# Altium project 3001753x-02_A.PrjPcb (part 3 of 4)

## Sheet 12 - MIPI to HDMI bridge.SchDoc: MIPI to HDMI bridge
size A3; PageSetup: Record=PageOptions¦CenterHorizontal=True¦CenterVertical=True¦PrintScale=0.70¦XCorrection=1.00¦YCorrection=1.00¦PrintKind=0¦BorderSize=5000000¦LeftOffset=0¦BottomOffset=0¦Orientation=2¦PaperLength=4200¦PaperWidth=2970¦Scale=100¦PaperSource=7¦PrintQuality=600¦MediaType=1¦DitherType=10¦PaperKind=A4¦PrintScaleMode=1; Author: Juan Anzola; SheetNumber: 12; SheetTotal: 20

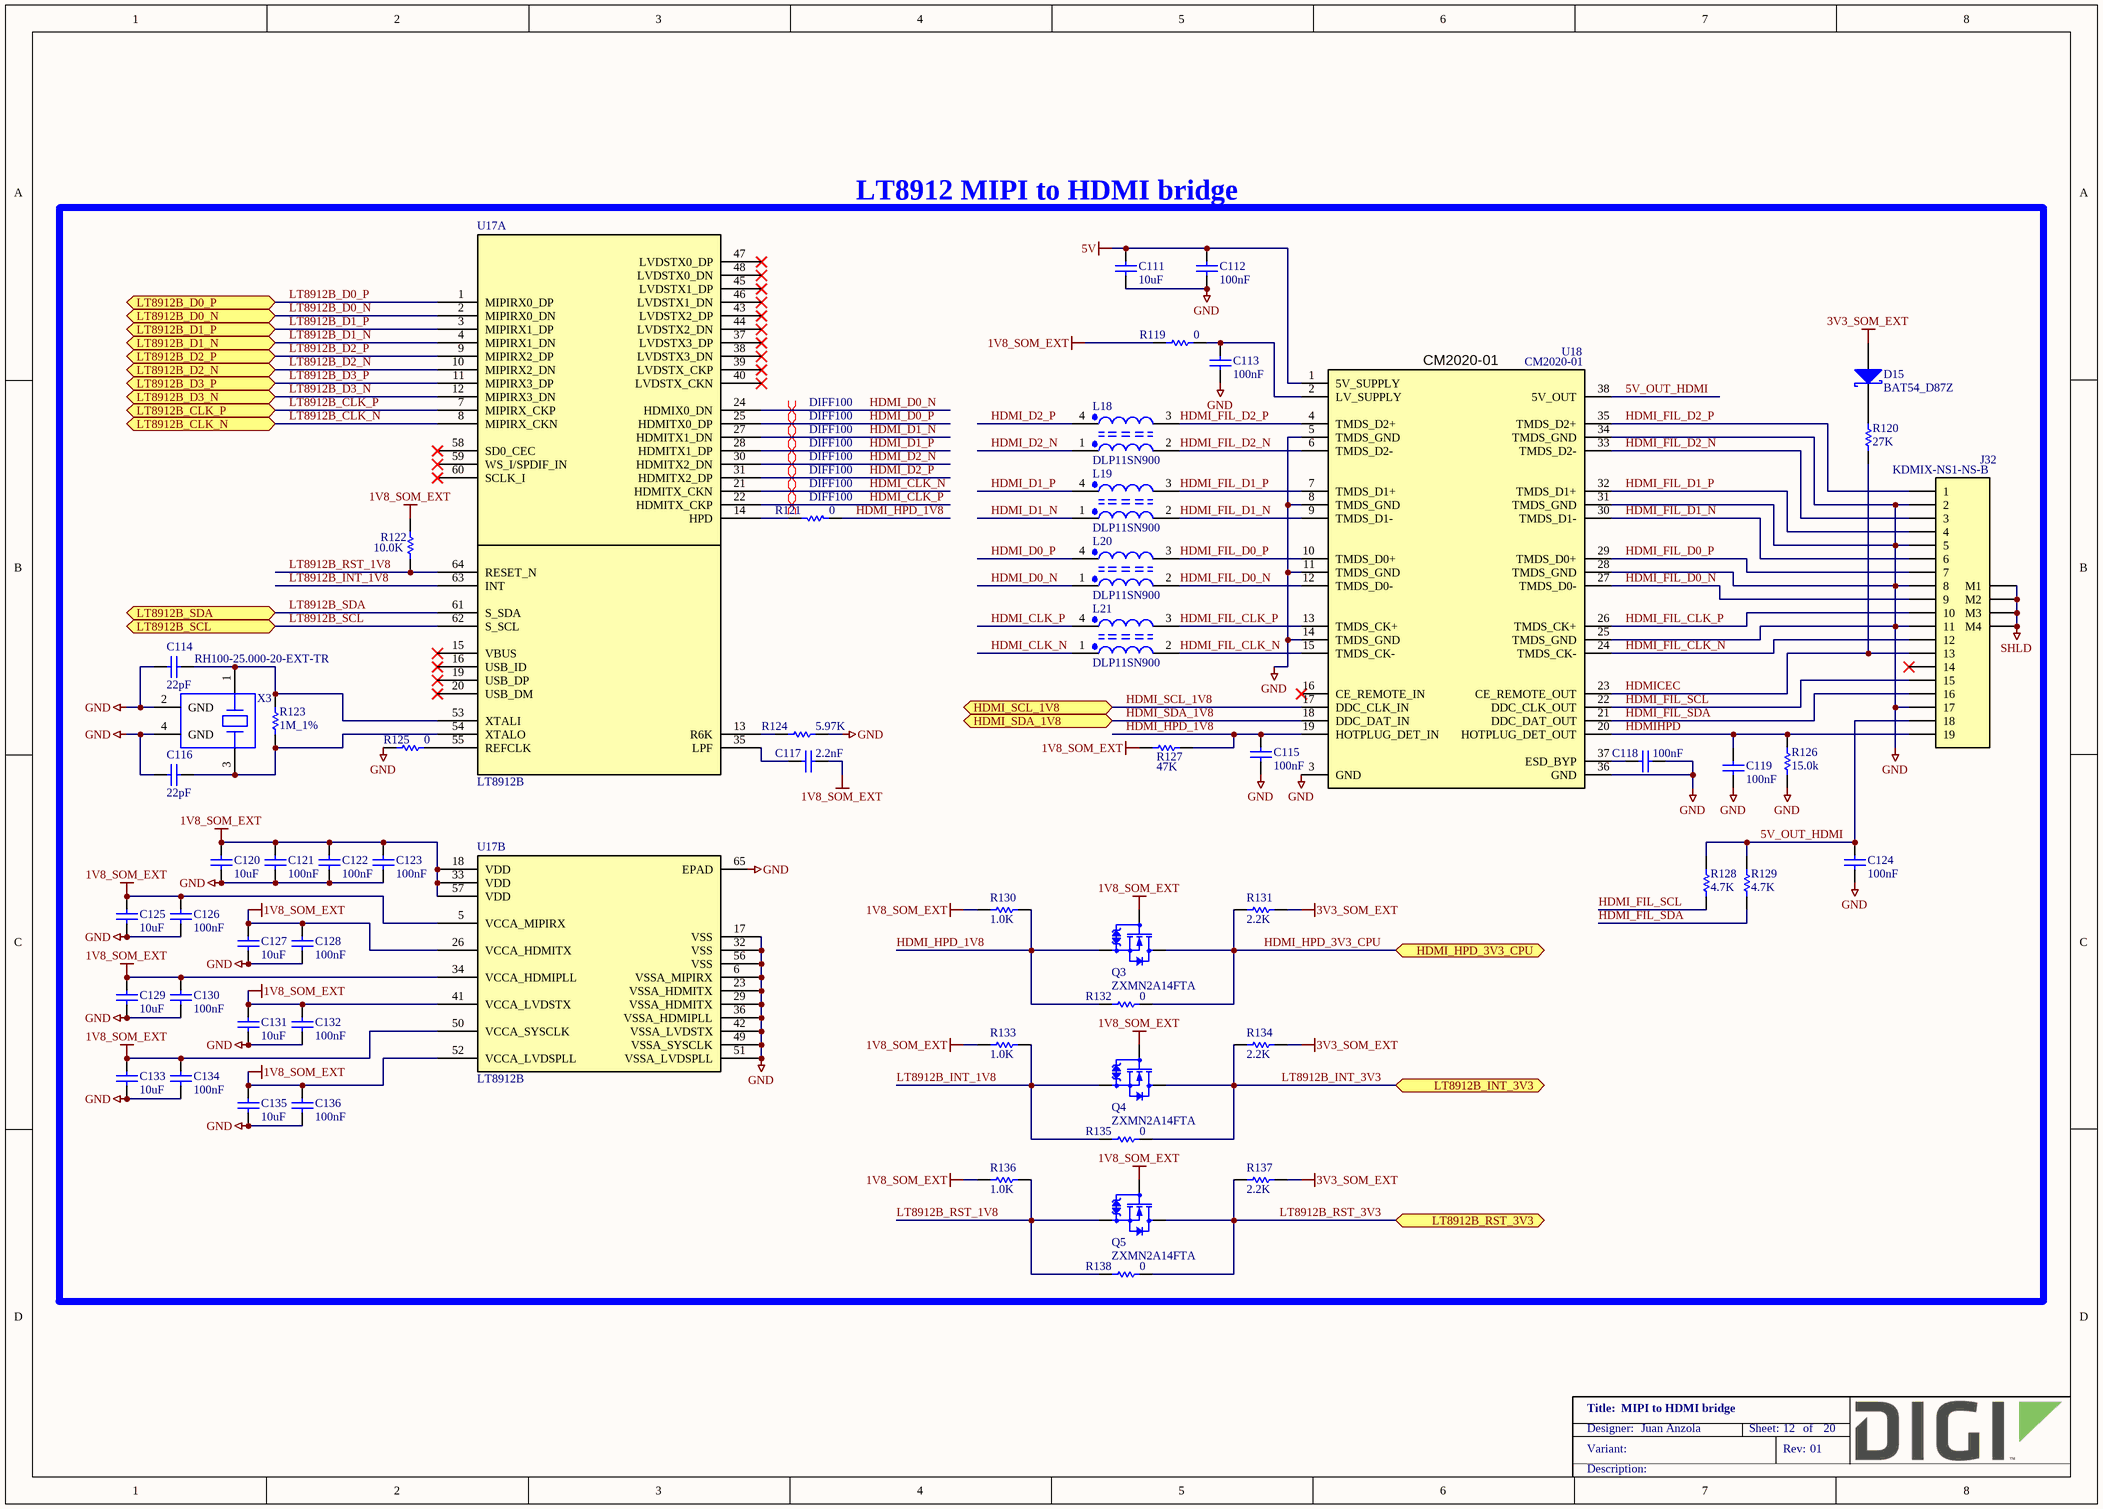
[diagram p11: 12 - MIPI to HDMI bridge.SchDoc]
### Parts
C111  10uF  [CAPC1005X55N]
C112  100nF  [CAPC1005X55N]
C113  100nF  [CAPC1005X55N]
C114  22pF  [CAPC1005X55N]
C115  100nF  [CAPC1005X55N]
C116  22pF  [CAPC1005X55N]
C117  2.2nF  [CAPC1608X90N]
C118  100nF  [CAPC1005X55N]
C119  100nF  [CAPC1005X55N]
C120  10uF  [CAPC1005X55N]
C121  100nF  [CAPC1005X55N]
C122  100nF  [CAPC1005X55N]
C123  100nF  [CAPC1005X55N]
C124  100nF  [CAPC1005X55N]
C125  10uF  [CAPC1005X55N]
C126  100nF  [CAPC1005X55N]
C127  10uF  [CAPC1005X55N]
C128  100nF  [CAPC1005X55N]
C129  10uF  [CAPC1005X55N]
C130  100nF  [CAPC1005X55N]
C131  10uF  [CAPC1005X55N]
C132  100nF  [CAPC1005X55N]
C133  10uF  [CAPC1005X55N]
C134  100nF  [CAPC1005X55N]
C135  10uF  [CAPC1005X55N]
C136  100nF  [CAPC1005X55N]
D15  BAT54_D87Z  [SOT95P240X110_AXK-3N]
J32  KDMIX-NS1-NS-B  [KYCON_KDMIX]
L18  DLP11SN900  [FIL_DLP11S]
L19  DLP11SN900  [FIL_DLP11S]
L20  DLP11SN900  [FIL_DLP11S]
L21  DLP11SN900  [FIL_DLP11S]
Q3  ZXMN2A14FTA  [SOT95P240X110_GSD-3N]
Q4  ZXMN2A14FTA  [SOT95P240X110_GSD-3N]
Q5  ZXMN2A14FTA  [SOT95P240X110_GSD-3N]
R119  0  [RESC1005X40N]
R120  27K  [RESC1005X40N]
R121  0  [RESC1005X40N]
R122  10.0K  [RESC1005X40N]
R123  1M_1%  [RESC1005X40N]
R124  5.97K  [RESC1005X40N]
R125  0  [RESC1005X40N]
R126  15.0k  [RESC1005X40N]
R127  47K  [RESC1005X40N]
R128  4.7K  [RESC1005X40N]
R129  4.7K  [RESC1005X40N]
R130  1.0K  [RESC1005X40N]
R131  2.2K  [RESC1005X40N]
R132  0  [RESC1005X40N]
R133  1.0K  [RESC1005X40N]
R134  2.2K  [RESC1005X40N]
R135  0  [RESC1005X40N]
R136  1.0K  [RESC1005X40N]
R137  2.2K  [RESC1005X40N]
R138  0  [RESC1005X40N]
U17  LT8912B  [QFN40P750X750X80-65T620N]  (parts A,B of 2)
U18  CM2020-01  [SOP50P640X120-38N]
X3  RH100-25.000-20-EXT-TR  [OSC210P320X250X90-4N]

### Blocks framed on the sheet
LT8912 MIPI to HDMI bridge: C111-C136 D15 J32 L18-L21 Q3-Q5 R119-R138 U17 U18 X3

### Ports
HDMI_HPD_3V3_CPU (bidir), HDMI_SCL_1V8 (bidir), HDMI_SDA_1V8 (bidir), LT8912B_CLK_N (bidir), LT8912B_CLK_P (bidir), LT8912B_D0_N (bidir), LT8912B_D0_P (bidir), LT8912B_D1_N (bidir), LT8912B_D1_P (bidir), LT8912B_D2_N (bidir), LT8912B_D2_P (bidir), LT8912B_D3_N (bidir), LT8912B_D3_P (bidir), LT8912B_INT_3V3 (bidir), LT8912B_RST_3V3 (bidir), LT8912B_SCL (bidir), LT8912B_SDA (bidir)

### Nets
1V8_SOM_EXT: C117.2 C120.2 C121.2 C122.2 C123.2 C125.2 C126.2 C127.2 C128.2 C129.2 C130.2 C131.2 C132.2 C133.2 C134.2 C135.2 C136.2 Q3.G Q4.G Q5.G R119.2 R122.1 R127.1 R130.2 R133.2 R136.2 U17.5(VCCA_MIPIRX) U17.18(VDD) U17.26(VCCA_HDMITX) U17.33(VDD) U17.34(VCCA_HDMIPLL) U17.41(VCCA_LVDSTX) U17.50(VCCA_SYSCLK) U17.52(VCCA_LVDSPLL) U17.57(VDD)
3V3_SOM_EXT: D15.A R131.2 R134.2 R137.2
5V: C111.2 C112.2 U18.1(5V_SUPPLY)
GND: C111.1 C112.1 C113.1 C114.1 C115.1 C116.1 C118.1 C119.1 C120.1 C121.1 C122.1 C123.1 C124.1 C125.1 C126.1 C127.1 C128.1 C129.1 C130.1 C131.1 C132.1 C133.1 C134.1 C135.1 C136.1 J32.2 J32.5 J32.8 J32.11 J32.17 R124.2 R125.1 R126.1 U17.6(VSSA_MIPIRX) U17.17(VSS) U17.23(VSSA_HDMITX) U17.29(VSSA_HDMITX) U17.32(VSS) U17.36(VSSA_HDMIPLL) U17.42(VSSA_LVDSTX) U17.49(VSSA_SYSCLK) U17.51(VSSA_LVDSPLL) U17.56(VSS) U17.65(EPAD) U18.3(GND) U18.5(TMDS_GND) U18.8(TMDS_GND) U18.11(TMDS_GND) U18.14(TMDS_GND) U18.25(TMDS_GND) U18.28(TMDS_GND) U18.31(TMDS_GND) U18.34(TMDS_GND) U18.36(GND) X3.2(GND) X3.4(GND)
SHLD: J32.M1 J32.M2 J32.M3 J32.M4
5V_OUT_HDMI: C124.2 J32.18 R128.1 R129.1 U18.38(5V_OUT)
HDMI_CLK_N: L21.1 U17.21(HDMITX_CKN)
HDMI_CLK_P: L21.4 U17.22(HDMITX_CKP)
HDMI_D0_N: L20.1 U17.24(HDMIX0_DN)
HDMI_D0_P: L20.4 U17.25(HDMITX0_DP)
HDMI_D1_N: L19.1 U17.27(HDMITX1_DN)
HDMI_D1_P: L19.4 U17.28(HDMITX1_DP)
HDMI_D2_N: L18.1 U17.30(HDMITX2_DN)
HDMI_D2_P: L18.4 U17.31(HDMITX2_DP)
HDMI_FIL_CLK_N: J32.12 L21.2 U18.15(TMDS_CK-) U18.24(TMDS_CK-)
HDMI_FIL_CLK_P: J32.10 L21.3 U18.13(TMDS_CK+) U18.26(TMDS_CK+)
HDMI_FIL_D0_N: J32.9 L20.2 U18.12(TMDS_D0-) U18.27(TMDS_D0-)
HDMI_FIL_D0_P: J32.7 L20.3 U18.10(TMDS_D0+) U18.29(TMDS_D0+)
HDMI_FIL_D1_N: J32.6 L19.2 U18.9(TMDS_D1-) U18.30(TMDS_D1-)
HDMI_FIL_D1_P: J32.4 L19.3 U18.7(TMDS_D1+) U18.32(TMDS_D1+)
HDMI_FIL_D2_N: J32.3 L18.2 U18.6(TMDS_D2-) U18.33(TMDS_D2-)
HDMI_FIL_D2_P: J32.1 L18.3 U18.4(TMDS_D2+) U18.35(TMDS_D2+)
HDMI_FIL_SCL: J32.15 R128.2 U18.22(DDC_CLK_OUT)
HDMI_FIL_SDA: J32.16 R129.2 U18.21(DDC_DAT_OUT)
HDMI_HPD_1V8: C115.2 Q3.S R121.1 R127.2 R130.1 R132.1 U18.19(HOTPLUG_DET_IN)
HDMI_HPD_3V3_CPU: Q3.D R131.1 R132.2 ; port HDMI_HPD_3V3_CPU
HDMI_SCL_1V8: U18.17(DDC_CLK_IN) ; port HDMI_SCL_1V8
HDMI_SDA_1V8: U18.18(DDC_DAT_IN) ; port HDMI_SDA_1V8
HDMICEC: J32.13 R120.2 U18.23(CE_REMOTE_OUT)
HDMIHPD: C119.2 J32.19 R126.2 U18.20(HOTPLUG_DET_OUT)
LT8912B_CLK_N: U17.8(MIPIRX_CKN) ; port LT8912B_CLK_N
LT8912B_CLK_P: U17.7(MIPIRX_CKP) ; port LT8912B_CLK_P
LT8912B_D0_N: U17.2(MIPIRX0_DN) ; port LT8912B_D0_N
LT8912B_D0_P: U17.1(MIPIRX0_DP) ; port LT8912B_D0_P
LT8912B_D1_N: U17.4(MIPIRX1_DN) ; port LT8912B_D1_N
LT8912B_D1_P: U17.3(MIPIRX1_DP) ; port LT8912B_D1_P
LT8912B_D2_N: U17.10(MIPIRX2_DN) ; port LT8912B_D2_N
LT8912B_D2_P: U17.9(MIPIRX2_DP) ; port LT8912B_D2_P
LT8912B_D3_N: U17.12(MIPIRX3_DN) ; port LT8912B_D3_N
LT8912B_D3_P: U17.11(MIPIRX3_DP) ; port LT8912B_D3_P
LT8912B_INT_1V8: Q4.S R133.1 R135.1 U17.63(INT)
LT8912B_INT_3V3: Q4.D R134.1 R135.2 ; port LT8912B_INT_3V3
LT8912B_RST_1V8: Q5.S R122.2 R136.1 R138.1 U17.64(RESET_N)
LT8912B_RST_3V3: Q5.D R137.1 R138.2 ; port LT8912B_RST_3V3
LT8912B_SCL: U17.62(S_SCL) ; port LT8912B_SCL
LT8912B_SDA: U17.61(S_SDA) ; port LT8912B_SDA
NetC113_2: C113.2 R119.1 U18.2(LV_SUPPLY)
NetC114_2: C114.2 R123.2 U17.53(XTALI) X3.1
NetC116_2: C116.2 R123.1 U17.54(XTALO) X3.3
NetC117_1: C117.1 U17.35(LPF)
NetC118_2: C118.2 U18.37(ESD_BYP)
NetD15_K: D15.K R120.1
NetR121_2: R121.2 U17.14(HPD)
NetR124_1: R124.1 U17.13(R6K)
NetR125_2: R125.2 U17.55(REFCLK)

Not connected (* = marked no-connect by the designer): J32 14*; U17 15(VBUS)* 16(USB_ID)* 19(USB_DP)* 20(USB_DM)* 37(LVDSTX3_DP)* 38(LVDSTX3_DN)* 39(LVDSTX_CKP)* 40(LVDSTX_CKN)* 43(LVDSTX2_DP)* 44(LVDSTX2_DN)* 45(LVDSTX1_DP)* 46(LVDSTX1_DN)* 47(LVDSTX0_DP)* 48(LVDSTX0_DN)* 58(SD0_CEC)* 59(WS_I/SPDIF_IN)* 60(SCLK_I)*; U18 16(CE_REMOTE_IN)*

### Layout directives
differential pair; net class DIFF100; differential pair class DIFF100: HDMI_CLK_N, HDMI_CLK_P, HDMI_D0_N, HDMI_D0_P, HDMI_D1_N, HDMI_D1_P, HDMI_D2_N, HDMI_D2_P

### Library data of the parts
C111 C120 C125 C127 C129 C131 C133 C135 = 1001168: CAP CER 10UF 10V 20% X5R 0402; Part_Type: Capacitor; Manufacturer: Samsung; Manufacturer_Part_Number: CL05A106MP5NUNC; Digi_PN: 14050689; Component_Life_Cycle_State: Reviewed; Area: 0.95; Project: CCWMX6_SBC board
C112 C113 C115 C118 C119 C121-C124 C126 C128 C130 C132 C134 C136 = 1000006: CAP 100nF 16V 10% X7R 0402; Part_Type: Capacitor; Manufacturer: Murata; Manufacturer_Part_Number: GRM155R71C104KA88D; Component_Life_Cycle_State: CAD Reviewed; Area: 0.95; Project: KITT; Tolerance: 10; Digi_PN: 14050552
C114 C116 = 1001166: CAP CER 22PF 50V 5% NP0 0402; Part_Type: Capacitor; Manufacturer: Murata; Manufacturer_Part_Number: GRM1555C1H220JA01D; Note: 14050749 = Digi No. for GE WDNU; Digi_PN: 14050367; Component_Life_Cycle_State: Reviewed; Area: 0,95; Project: CCWMX6_SBC board; Temp_Coef: C0G, NP0
C117 = 1002727: CAP CER 2200PF 50V X7R 5% 0603; Part_Type: Capacitor; Manufacturer: Kemet; Manufacturer_Part_Number: C0603C222J5RACTU; Digi_PN: 14050443; Component_Life_Cycle_State: Pending; Area: 2,27
D15 = 1001169: DIODE SCHOTTKY 30V 0.2A SOT23-3; Part_Type: IC; Manufacturer: Fairchild Semiconductor; Digi_PN: 17050507; Component_Life_Cycle_State: Reviewed; Area: 8; Project: CCWMX6_SBC board
J32 = 1001123: HDMI RECEPTACLE, SMT; Part_Type: Connector; Manufacturer: KYCON; Digi_PN: 18000451; Component_Life_Cycle_State: Reviewed; Area: 174; Project: CCWMX6_SBC board
L18-L21 = 1001014: CHOKE COIL COMMON MODE 150MA SMD; Part_Type: Inductor; Manufacturer: Murata; Manufacturer_Part_Number: DLP11SN900HL2L; Component_Life_Cycle_State: Reviewed; Area: 3.94; Project: ResMed RF Test Interface Board; Digi_PN: 21000531
Q3-Q5 = 1002855: MOSFET N-CH 20V 3.4A SOT23-3; Part_Type: Transistor; Manufacturer: Diodes, Inc.; Digi_PN: 17000304; Component_Life_Cycle_State: Pending
R119 R121 R125 = 1000076: RES 0.0 OHM 1/10W 0402 SMD; Part_Type: Resistor; Manufacturer: Panasonic - ECG; Manufacturer_Part_Number: ERJ-2GE0R00X; Digi_PN: 13050387; Component_Life_Cycle_State: Proven; Area: 0,95; Project: Adjustable Foundation; Power_WV_SRF: 10
R120 = 1001153: RES 27.0K OHM 1/16W 1% 0402 SMD; Part_Type: Resistor; Manufacturer: Yageo; Manufacturer_Part_Number: RC0402FR-0727KL; Digi_PN: 13050609; Component_Life_Cycle_State: Reviewed; Area: 0.95; Project: CCWMX6_SBC board
R122 = 1000537: RES 10.0K OHM 1/10W 1% 0402 SMD; Part_Type: Resistor; Manufacturer: Panasonic - ECG; Manufacturer_Part_Number: ERJ-2RKF1002X; Component_Life_Cycle_State: CAD Reviewed; Area: 0.95; Project: KITT; Power_WV_SRF: 100; Digi_PN: 13051084
R123 = 1000971: RES 1.00M OHM 1/16W 1% 0402 SMD; Part_Type: Resistor; Manufacturer: Yageo; Manufacturer_Part_Number: RC0402FR-071ML; Note: 13051098 = Digi No. for GE WDNU; Digi_PN: 13050561; Component_Life_Cycle_State: Reviewed; Area: 0,95; Power_WV_SRF: 63; Tolerance: 1
R124 = 1002748: RES 5.97K OHM 0.1% 1/10W 0402; Part_Type: Resistor; Manufacturer: Vishay Dale; Manufacturer_Part_Number: TNPW04025K97BEED; Digi_PN: 13000099; Component_Life_Cycle_State: Created; Area: 0,95
R126 = 1000174: RES 15.0K OHM 1/10W 1% 0402 SMD; Part_Type: Resistor; Manufacturer: Panasonic - ECG; Manufacturer_Part_Number: ERJ-2RKF1502X; Component_Life_Cycle_State: CAD Reviewed; Area: 0.95; Project: KITT; Power_WV_SRF: 10; Digi_PN: 13050446
R127 = 1001155: RES 47.0K OHM 1/16W 1% 0402 SMD; Part_Type: Resistor; Manufacturer: Vishay Dale; Manufacturer_Part_Number: CRCW040247K0FKED; Digi_PN: 13050646; Component_Life_Cycle_State: Reviewed; Area: 0.95; Project: CCWMX6_SBC board
R128 R129 = 1000038: RES 4.7K OHM 1/10W 5% 0402 SMD; Part_Type: Resistor; Manufacturer: Panasonic - ECG; Manufacturer_Part_Number: ERJ-2GEJ472X; Component_Life_Cycle_State: Proven; Area: 0.95; Project: Adjustable Foundation; Power_WV_SRF: 100; Tolerance: 5; Digi_PN: 13050549
R130 R133 R136 = 1000079: RES 1.00K OHM 1/10W 1% 0402 SMD; Part_Type: Resistor; Manufacturer: Panasonic - ECG; Manufacturer_Part_Number: ERJ-2RKF1001X; Digi_PN: 13051085; Component_Life_Cycle_State: Proven; Area: 0,95; Project: Adjustable Foundation; Power_WV_SRF: 10
R131 R134 R137 = 1001156: RES 2.20K OHM 1/16W 1% 0402 SMD; Part_Type: Resistor; Manufacturer: Yageo; Manufacturer_Part_Number: RC0402FR-072K2L; Note: 13051099 = Digi No. for GE WDNU; Digi_PN: 13050699; Component_Life_Cycle_State: Reviewed; Area: 0,95
R132 R135 R138 = 1000076: RES 0.0 OHM 1/10W 0402 SMD; Part_Type: Resistor; Manufacturer: Panasonic - ECG; Manufacturer_Part_Number: ERJ-2GE0R00X; Digi_PN: 13050387; Component_Life_Cycle_State: Proven; Area: 0,95; Power_WV_SRF: 10
U17 = 1002722: MIPI DSI BRIDGE TO LVDS/HDMI SINGLE CHANNEL; Part_Type: IC; Manufacturer: Lontium Semiconductor; Digi_PN: 16000199; Component_Life_Cycle_State: Reviewed; Area: 76,04
U18 = 1001125: IC HDMI XMITTER PORT P/I 38TSSOP; Manufacturer: On Semiconductor; Digi_PN: 16051861; Component_Life_Cycle_State: Reviewed; Area: 43; Project: CCWMX6_SBC board
X3 = 1001497: SMCRY,25MHZ 50PPM 20PF RH100 EXT; Part_Type: Crystals-Oscillators; Manufacturer: Raltron; Digi_PN: 20000285; Component_Life_Cycle_State: Reviewed; Area: 3,2; Project: CCWMX6_SBC board

## Sheet 13 - USB HUB.SchDoc: USB HUB
size A3; PageSetup: Record=PageOptions¦CenterHorizontal=True¦CenterVertical=True¦PrintScale=0.70¦XCorrection=1.00¦YCorrection=1.00¦PrintKind=0¦BorderSize=5000000¦LeftOffset=0¦BottomOffset=0¦Orientation=2¦PaperLength=4200¦PaperWidth=2970¦Scale=100¦PaperSource=7¦PrintQuality=600¦MediaType=1¦DitherType=10¦PaperKind=A4¦PrintScaleMode=1; Author: Juan Anzola; SheetNumber: 13; SheetTotal: 20

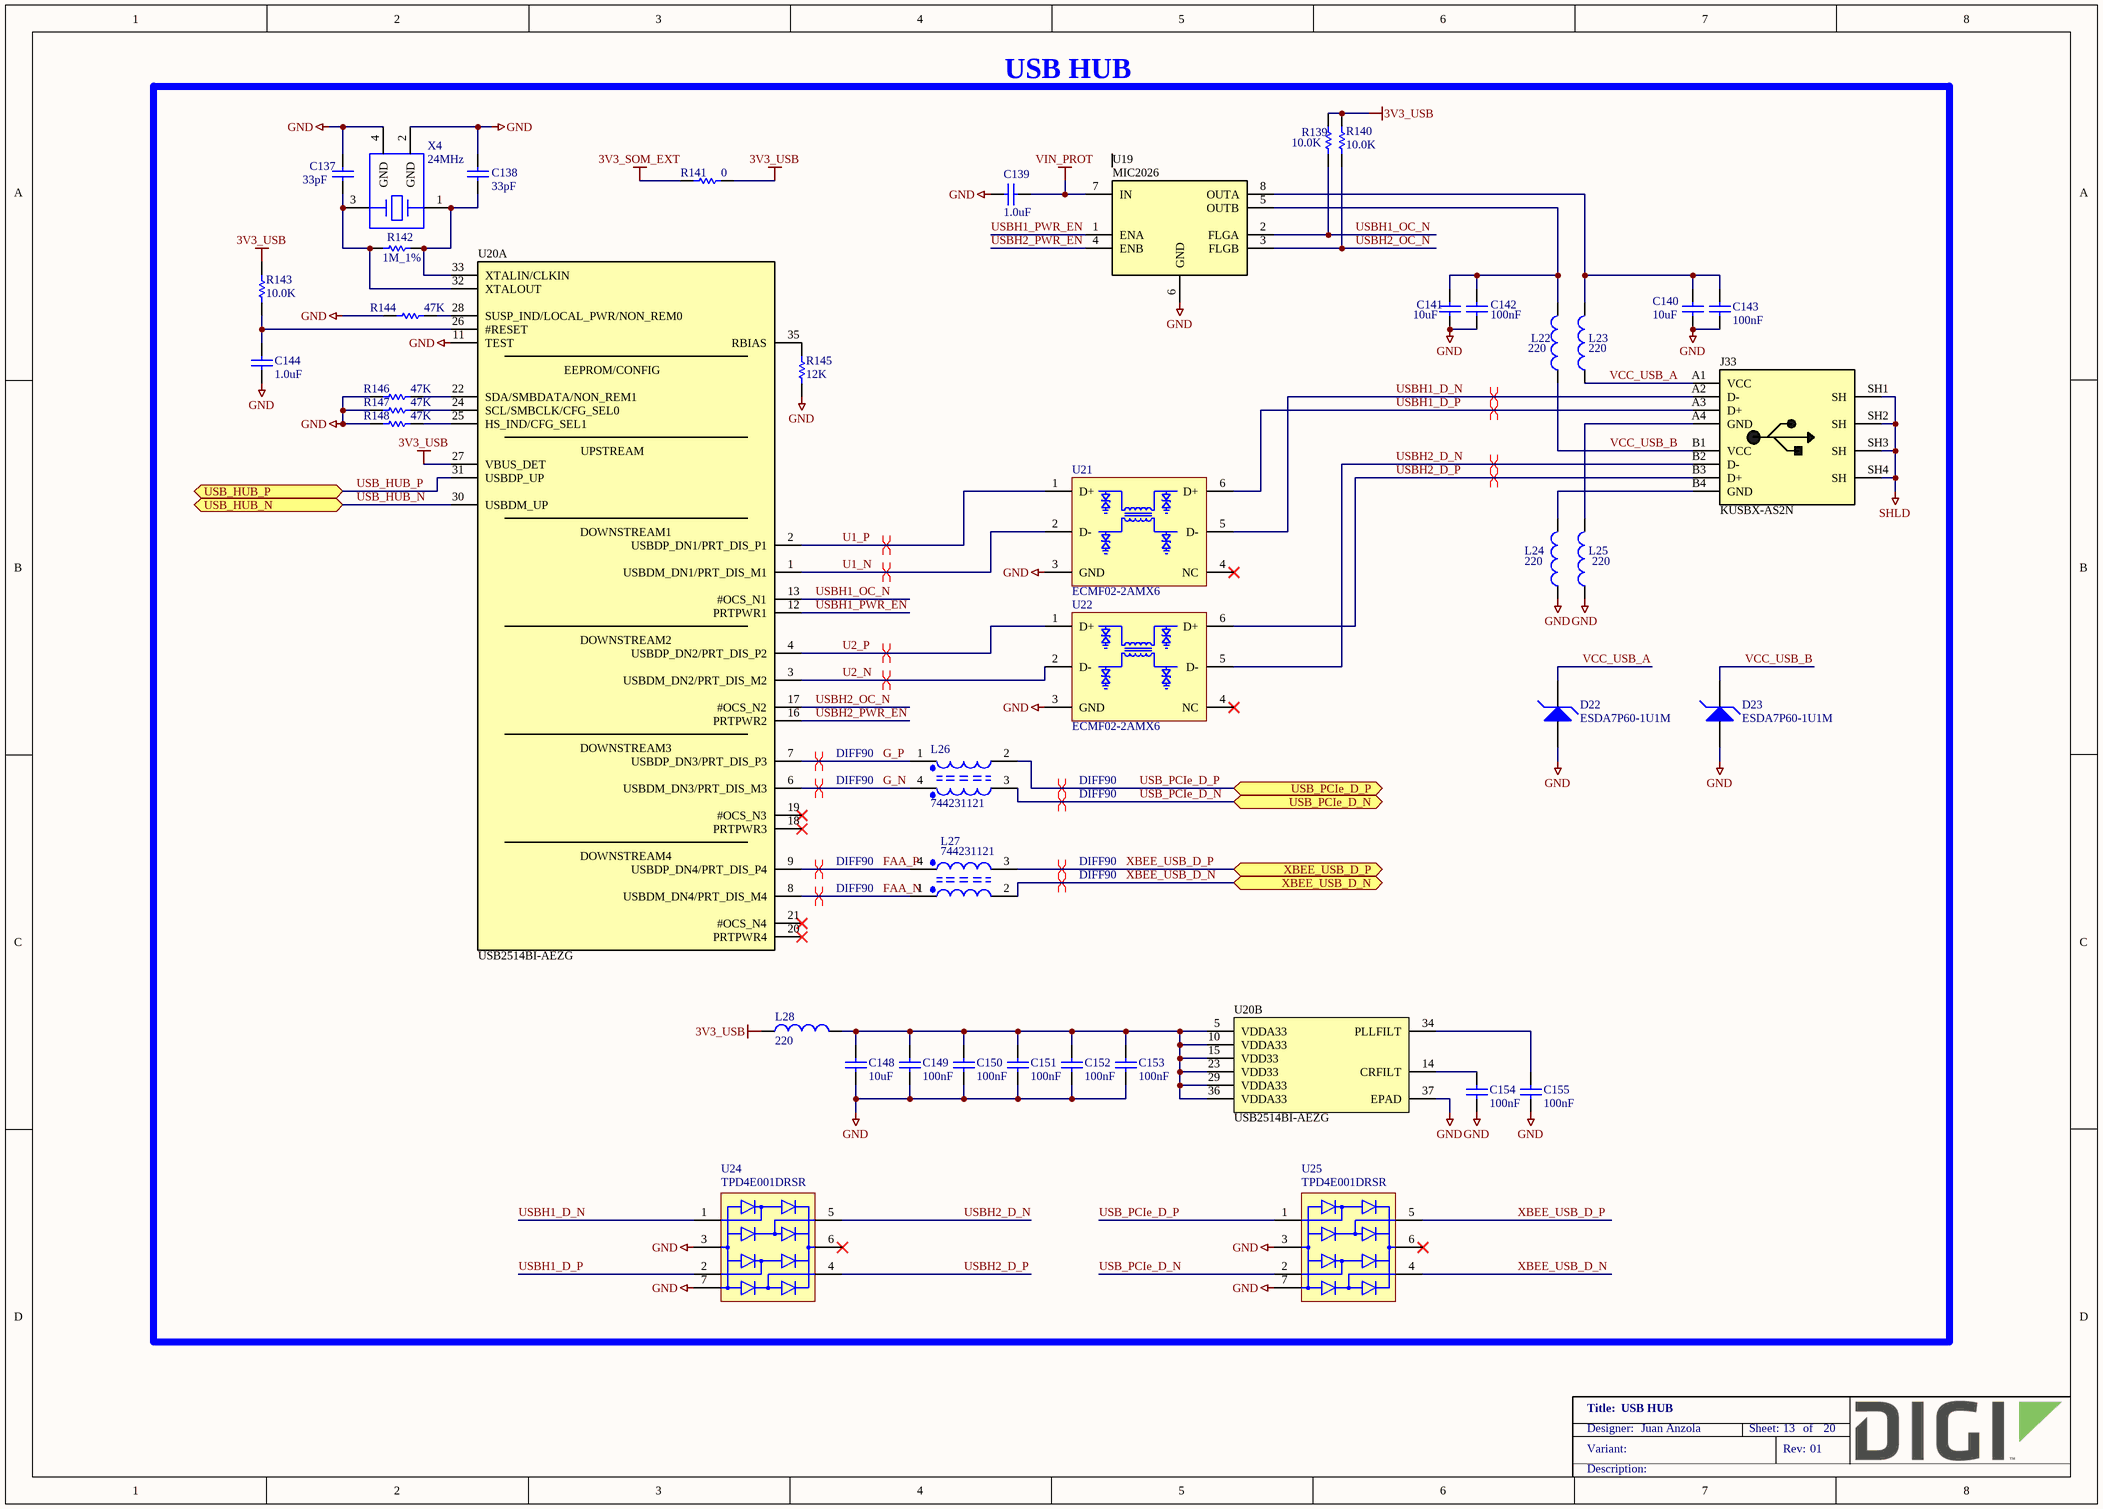
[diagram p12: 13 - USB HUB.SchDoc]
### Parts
C137  33pF  [CAPC1005X55N]
C138  33pF  [CAPC1005X55N]
C139  1.0uF  [CAPC1005X55N]
C140  10uF  [CAPC1005X55N]
C141  10uF  [CAPC1005X55N]
C142  100nF  [CAPC1005X55N]
C143  100nF  [CAPC1005X55N]
C144  1.0uF  [CAPC1005X55N]
C148  10uF  [CAPC1005X55N]
C149  100nF  [CAPC1005X55N]
C150  100nF  [CAPC1005X55N]
C151  100nF  [CAPC1005X55N]
C152  100nF  [CAPC1005X55N]
C153  100nF  [CAPC1005X55N]
C154  100nF  [CAPC1005X55N]
C155  100nF  [CAPC1005X55N]
D22  ESDA7P60-1U1M  [IND_1610]
D23  ESDA7P60-1U1M  [IND_1610]
J33  KUSBX-AS2N  [KYCON_KUSBX-AS2N_Flex]
L22  220  [INDC2013X110N]
L23  220  [INDC2013X110N]
L24  220  [INDC2013X110N]
L25  220  [INDC2013X110N]
L26  744231121  [FIL_DLW21H]
L27  744231121  [FIL_DLW21H]
L28  220  [INDC2013X110N]
R139  10.0K  [RESC1005X40N]
R140  10.0K  [RESC1005X40N]
R141  0  [RESC1609X55N]
R142  1M_1%  [RESC1005X40N]
R143  10.0K  [RESC1005X40N]
R144  47K  [RESC1005X40N]
R145  12K  [RESC1609X55N]
R146  47K  [RESC1005X40N]
R147  47K  [RESC1005X40N]
R148  47K  [RESC1005X40N]
U19  MIC2026  [SOIC127P600X175-8N]
U20  USB2514BI-AEZG  [QFN50P600X600X100-37AN]  (parts A,B of 2)
U21  ECMF02-2AMX6  [QFN_6L_1.7mmX1.5mm_STM]
U22  ECMF02-2AMX6  [QFN_6L_1.7mmX1.5mm_STM]
U24  TPD4E001DRSR  [SON95P300X300X80-7N]
U25  TPD4E001DRSR  [SON95P300X300X80-7N]
X4  24MHz  [XTAL_C3E-3427]

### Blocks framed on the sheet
USB HUB: C137-C144 C148-C155 D22 D23 J33 L22-L28 R139-R148 U19-U22 U24 U25 X4

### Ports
USB_HUB_N (bidir), USB_HUB_P (bidir), USB_PCIe_D_N (bidir), USB_PCIe_D_P (bidir), XBEE_USB_D_N (bidir), XBEE_USB_D_P (bidir)

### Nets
3V3_SOM_EXT: R141.1
3V3_USB: L28.2 R139.2 R140.2 R141.2 R143.2 U20.27(VBUS_DET)
GND: C137.2 C138.2 C139.2 C140.1 C141.1 C142.1 C143.1 C144.1 C148.1 C149.1 C150.1 C151.1 C152.1 C153.1 C154.1 C155.1 D22.A D23.A L24.1 L25.1 R144.2 R145.1 R146.1 R147.1 R148.1 U19.6(GND) U20.11(TEST) U20.37(EPAD) U21.3(GND) U22.3(GND) U24.3(GND) U24.7(GND) U25.3(GND) U25.7(GND) X4.2(GND) X4.4(GND)
SHLD: J33.SH1(SH) J33.SH2(SH) J33.SH3(SH) J33.SH4(SH)
VIN_PROT: C139.1 U19.7(IN)
FAA_N: L27.1 U20.8(USBDM_DN4/PRT_DIS_M4)
FAA_P: L27.4 U20.9(USBDP_DN4/PRT_DIS_P4)
G_N: L26.4 U20.6(USBDM_DN3/PRT_DIS_M3)
G_P: L26.1 U20.7(USBDP_DN3/PRT_DIS_P3)
U1_N: U20.1(USBDM_DN1/PRT_DIS_M1) U21.2(D-)
U1_P: U20.2(USBDP_DN1/PRT_DIS_P1) U21.1(D+)
U2_N: U20.3(USBDM_DN2/PRT_DIS_M2) U22.2(D-)
U2_P: U20.4(USBDP_DN2/PRT_DIS_P2) U22.1(D+)
USB_HUB_N: U20.30(USBDM_UP) ; port USB_HUB_N
USB_HUB_P: U20.31(USBDP_UP) ; port USB_HUB_P
USB_PCIe_D_N: L26.3 U25.2(I/O) ; port USB_PCIe_D_N
USB_PCIe_D_P: L26.2 U25.1(I/O) ; port USB_PCIe_D_P
USBH1_D_N: J33.A2(D-) U21.5(D-) U24.1(I/O)
USBH1_D_P: J33.A3(D+) U21.6(D+) U24.2(I/O)
USBH1_OC_N: R139.1 U19.2(FLGA) U20.13(#OCS_N1)
USBH1_PWR_EN: U19.1(ENA) U20.12(PRTPWR1)
USBH2_D_N: J33.B2(D-) U22.5(D-) U24.5(I/O)
USBH2_D_P: J33.B3(D+) U22.6(D+) U24.4(I/O)
USBH2_OC_N: R140.1 U19.3(FLGB) U20.17(#OCS_N2)
USBH2_PWR_EN: U19.4(ENB) U20.16(PRTPWR2)
VCC_USB_A: D22.K J33.A1(VCC) L23.1
VCC_USB_B: D23.K J33.B1(VCC) L22.1
XBEE_USB_D_N: L27.2 U25.4(I/O) ; port XBEE_USB_D_N
XBEE_USB_D_P: L27.3 U25.5(I/O) ; port XBEE_USB_D_P
NetC137_1: C137.1 R142.1 U20.32(XTALOUT) X4.3
NetC138_1: C138.1 R142.2 U20.33(XTALIN/CLKIN) X4.1
NetC140_2: C140.2 C143.2 L23.2 U19.8(OUTA)
NetC141_2: C141.2 C142.2 L22.2 U19.5(OUTB)
NetC144_2: C144.2 R143.1 U20.26(#RESET)
NetC148_2: C148.2 C149.2 C150.2 C151.2 C152.2 C153.2 L28.1 U20.5(VDDA33) U20.10(VDDA33) U20.15(VDD33) U20.23(VDD33) U20.29(VDDA33) U20.36(VDDA33)
NetC154_2: C154.2 U20.14(CRFILT)
NetC155_2: C155.2 U20.34(PLLFILT)
NetJ33_A4: J33.A4(GND) L25.2
NetJ33_B4: J33.B4(GND) L24.2
NetR144_1: R144.1 U20.28(SUSP_IND/LOCAL_PWR/NON_REM0)
NetR145_2: R145.2 U20.35(RBIAS)
NetR146_2: R146.2 U20.22(SDA/SMBDATA/NON_REM1)
NetR147_2: R147.2 U20.24(SCL/SMBCLK/CFG_SEL0)
NetR148_2: R148.2 U20.25(HS_IND/CFG_SEL1)

Not connected (* = marked no-connect by the designer): U20 18(PRTPWR3)* 19(#OCS_N3)* 20(PRTPWR4)* 21(#OCS_N4)*; U21 4(NC)*; U22 4(NC)*; U24 6(VCC)*; U25 6(VCC)*

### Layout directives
differential pair; differential pair class DIFF90: U1_N, U1_P, U2_N, U2_P, USBH1_D_N, USBH1_D_P, USBH2_D_N, USBH2_D_P
differential pair; net class DIFF90; differential pair class DIFF90: FAA_N, FAA_P, G_N, G_P, USB_PCIe_D_N, USB_PCIe_D_P, XBEE_USB_D_N, XBEE_USB_D_P

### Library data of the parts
C137 C138 = 1002646: CAP CER 33PF 50V C0G/NP0 0402; Part_Type: Capacitor; Manufacturer: Murata; Manufacturer_Part_Number: GCM1555C1H330JA16D; Digi_PN: 14050400; Component_Life_Cycle_State: Reviewed; Area: 2,12; Voltage: 50; Tolerance: 5%
C139 C144 = 1001167: CAP CER 1UF 10V 10% X5R 0402; Part_Type: Capacitor; Manufacturer: Murata; Manufacturer_Part_Number: GRM155R61A105KE15D; Digi_PN: 14050399; Component_Life_Cycle_State: Reviewed; Area: 0.95; Project: CCWMX6_SBC board
C140 C141 C148 = 1001168: as C111 on sheet 12 - MIPI to HDMI bridge
C142 C143 C149-C155 = 1000006: as C112 on sheet 12 - MIPI to HDMI bridge
D22 D23 = 1002861: TVS DIODE 5VWM 11.6VC 1610; Part_Type: Diodes; Manufacturer: STMicroelectronics; Digi_PN: 17000341; Component_Life_Cycle_State: Pending
J33 = 1001121: USB Stacked Dual A type; Part_Type: Connector; Manufacturer: KYCON; Digi_PN: 18000276; Component_Life_Cycle_State: Reviewed; Area: 164; Project: CCWMX6_SBC board
L22-L25 L28 = 1001174: FERRITE BEAD 220 OHM 2.0A 0805; Manufacturer: Wurth Electronics Inc; Manufacturer_Part_Number: 742792022; Digi_PN: 21000146; Component_Life_Cycle_State: Reviewed; Area: 4.24; Project: CCWMX6_SBC board
L26 L27 = 1001173: CHOKE COM MODE 120 OHM .37A; Part_Type: Inductor; Manufacturer: Wurth Electronics Inc; Digi_PN: 21000143; Component_Life_Cycle_State: Reviewed; Area: 2.4; Project: CCWMX6_SBC board
R139 R140 R143 = 1000537: as R122 on sheet 12 - MIPI to HDMI bridge
R141 = 1000208: RES 0.0 OHM 1/10W 0603; Part_Type: Resistor; Manufacturer: Panasonic - ECG; Manufacturer_Part_Number: ERJ-3GEY0R00V; Note: 13051103 = Digi No. for GE WDNU; Digi_PN: 13050568; Component_Life_Cycle_State: Reviewed; Area: 2.5; Project: Adjustable Foundation; Voltage: 75V
R142 = 1000971: RES 1.00M OHM 1/16W 1% 0402 SMD; Part_Type: Resistor; Manufacturer: Yageo; Manufacturer_Part_Number: RC0402FR-071ML; Digi_PN: 13050561; Component_Life_Cycle_State: Reviewed; Area: 0.95; Project: ConnectCore i.MX6 module; Power_WV_SRF: 63; Tolerance: 1; Note: 13051098 = Digi No. for GE WDNU
R144 R146-R148 = 1001155: as R127 on sheet 12 - MIPI to HDMI bridge
R145 = 1001200: RES 12.0K OHM 1/10W 1% 0603 SMD; Part_Type: Resistor; Manufacturer: Yageo; Manufacturer_Part_Number: RC0603FR-0712KL; Digi_PN: 13050531; Component_Life_Cycle_State: Reviewed; Area: 2.5; Project: LuCoV2; Power_WV_SRF: 100; Tolerance: 1
U19 = 1001143: IC SW DISTRIBUTION 2CHAN 8SOIC; Manufacturer: Micrel; Manufacturer_Part_Number: MIC2026-1YM; Digi_PN: 16051879; Component_Life_Cycle_State: Reviewed; Area: 29.58; Project: CCWMX6_SBC board
U20 = 1001114: 4-PORT USB 2.0 HUB CTRLR 36VQFN; Part_Type: IC; Manufacturer: SMSC; Digi_PN: 16051280; Component_Life_Cycle_State: Reviewed; Area: 36; Project: CCWMX6_SBC board
U21 U22 = 1002838: SMIC, COMMON MODE USB2.0/MIPI + ESD, QFN6, -40/+125°C
U24 U25 = 1001265: TVS DIODE 5.5VWM 6SON; Part_Type: IC; Manufacturer: Texas Instruments; Digi_PN: 17050690; Component_Life_Cycle_State: Reviewed; Area: 10; Project: CCWMX6_SBC board; Note: 17050839 = Digi No. for GE WDNU
X4 = 1001134: CRYSTAL 24MHZ 18PF SMD; Part_Type: Crystals-Oscillators; Manufacturer: Aker; Manufacturer_Part_Number: C3E-24.000-18-3030-X-R; Digi_PN: 20000223; Component_Life_Cycle_State: Reviewed; Area: 9.18; Project: CCWMX6_SBC board

## Sheet 14 - USB Type C.SchDoc: USB Type C, USB mciroAB
size A3; PageSetup: Record=PageOptions¦CenterHorizontal=True¦CenterVertical=True¦PrintScale=0.70¦XCorrection=1.00¦YCorrection=1.00¦PrintKind=0¦BorderSize=5000000¦LeftOffset=0¦BottomOffset=0¦Orientation=2¦PaperLength=4200¦PaperWidth=2970¦Scale=100¦PaperSource=7¦PrintQuality=600¦MediaType=1¦DitherType=10¦PaperKind=A4¦PrintScaleMode=1; Author: Juan Anzola; SheetNumber: 14; SheetTotal: 20

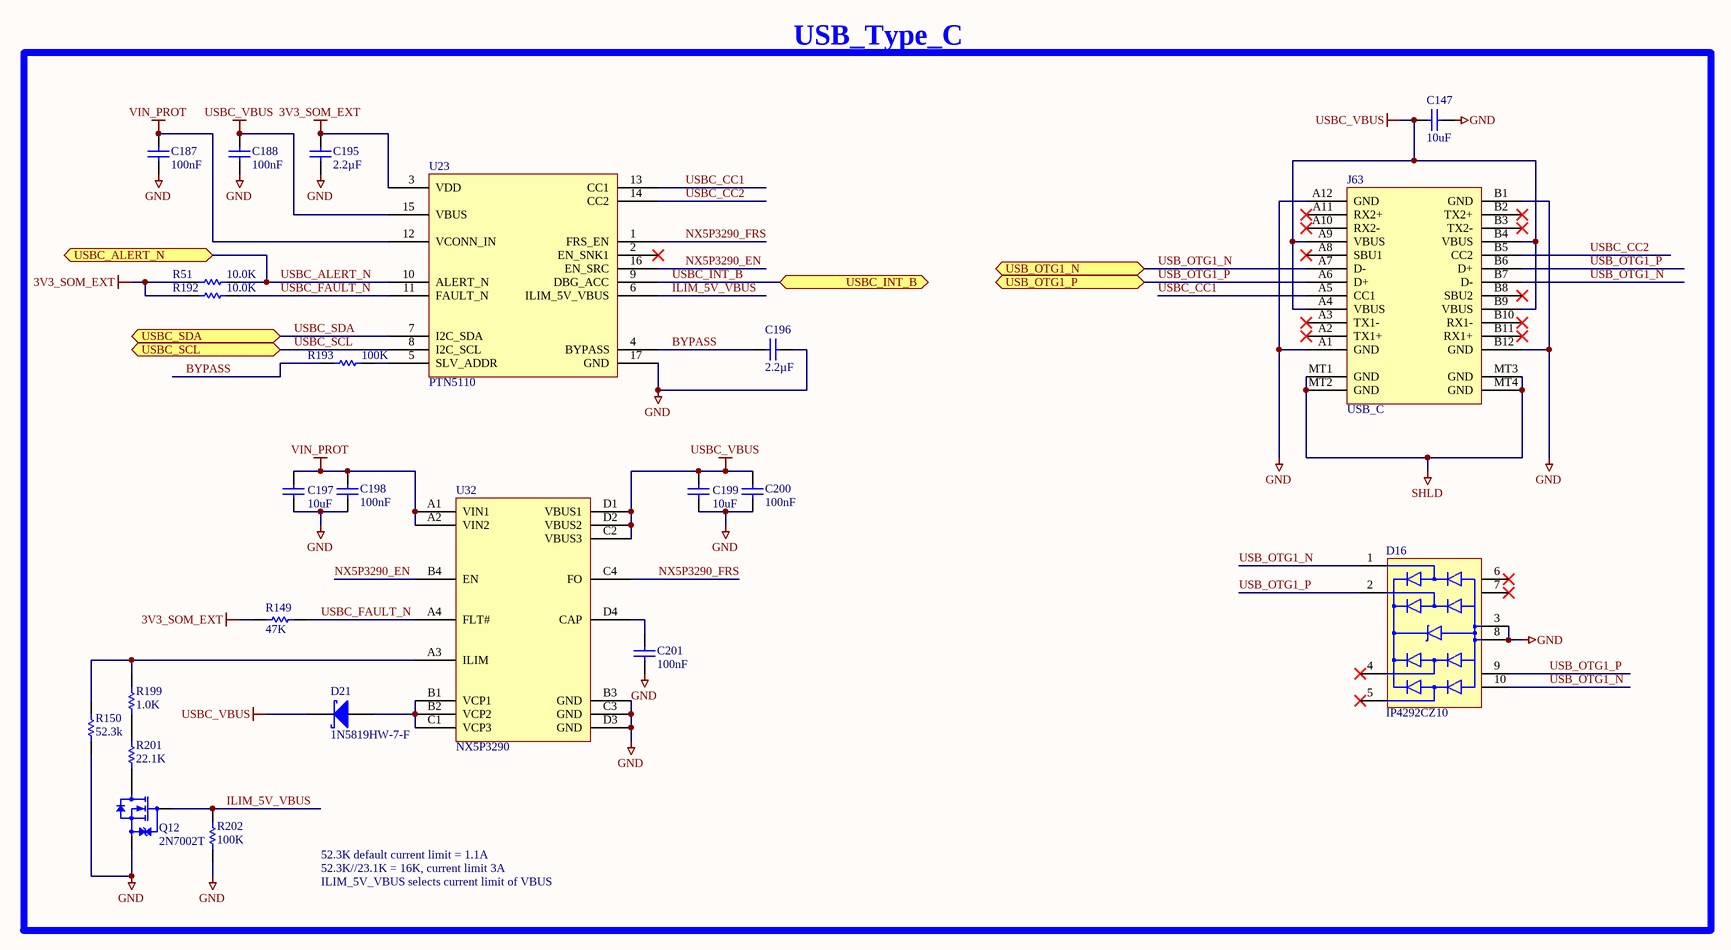
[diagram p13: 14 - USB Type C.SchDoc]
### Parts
C147  10uF  [CAPC1005X55N]
C187  100nF  [CAPC1005X55N]
C188  100nF  [CAPC1005X55N]
C195  2.2µF  [CAPC1005X55L]
C196  2.2µF  [CAPC1005X55L]
C197  10uF  [CAPC1005X55N]
C198  100nF  [CAPC1005X55N]
C199  10uF  [CAPC1005X55N]
C200  100nF  [CAPC1005X55N]
C201  100nF  [CAPC1005X55N]
D16  IP4292CZ10  [SON50P250X100X50-10N]
D21  1N5819HW-7-F  [SOD3716X135N]
J63  USB_C  [MOLEX_201267-0005]
Q12  2N7002T  [SOTFL50P160X80_GSD-3N]
R51  10.0K  [RESC1005X40N]
R149  47K  [RESC1005X40N]
R150  52.3k  [RESC1005X40N]
R192  10.0K  [RESC1005X40N]
R193  100K  [RESC1005X40N]
R199  1.0K  [RESC1005X40N]
R201  22.1K  [RESC1005X40N]
R202  100K  [RESC1005X40N]
U23  PTN5110  [QFN40P260X260X40-17T100X110N]
U32  NX5P3290  [BGA16N50P4X4_205X205X59B32N]

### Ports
USB_OTG1_N (bidir), USB_OTG1_P (bidir), USBC_ALERT_N (bidir), USBC_INT_B (bidir), USBC_SCL (bidir), USBC_SDA (bidir)

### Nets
3V3_SOM_EXT: C195.2 R51.1 R149.1 R192.1 U23.3(VDD)
GND: C147.1 C187.1 C188.1 C195.1 C196.1 C197.1 C198.1 C199.1 C200.1 C201.1 D16.3(GND) D16.8(GND) J63.A1(GND) J63.A12(GND) J63.B1(GND) J63.B12(GND) Q12.S R150.1 R202.1 U23.17(GND) U32.B3(GND) U32.C3(GND) U32.D3(GND)
SHLD: J63.MT1(GND) J63.MT2(GND) J63.MT3(GND) J63.MT4(GND)
USBC_VBUS: C147.2 C188.2 C199.2 C200.2 D21.K J63.A4(VBUS) J63.A9(VBUS) J63.B4(VBUS) J63.B9(VBUS) U23.15(VBUS) U32.C2(VBUS3) U32.D1(VBUS1) U32.D2(VBUS2)
VIN_PROT: C187.2 C197.2 C198.2 U23.12(VCONN_IN) U32.A1(VIN1) U32.A2(VIN2)
BYPASS: C196.2 R193.1 U23.4(BYPASS)
ILIM_5V_VBUS: Q12.G R202.2 U23.6(ILIM_5V_VBUS)
NX5P3290_EN: U23.16(EN_SRC) U32.B4(EN)
NX5P3290_FRS: U23.1(FRS_EN) U32.C4(FO)
USB_OTG1_N: D16.1(CH1) D16.10(NC) J63.A7(D-) J63.B7(D-) ; port USB_OTG1_N
USB_OTG1_P: D16.2(CH2) D16.9(NC) J63.A6(D+) J63.B6(D+) ; port USB_OTG1_P
USBC_ALERT_N: R51.2 U23.10(ALERT_N) ; port USBC_ALERT_N
USBC_CC1: J63.A5(CC1) U23.13(CC1)
USBC_CC2: J63.B5(CC2) U23.14(CC2)
USBC_FAULT_N: R149.2 R192.2 U23.11(FAULT_N) U32.A4(FLT#)
USBC_INT_B: U23.9(DBG_ACC) ; port USBC_INT_B
USBC_SCL: U23.8(I2C_SCL) ; port USBC_SCL
USBC_SDA: U23.7(I2C_SDA) ; port USBC_SDA
NetC201_2: C201.2 U32.D4(CAP)
NetD21_A: D21.A U32.B1(VCP1) U32.B2(VCP2) U32.C1(VCP3)
NetQ12_D: Q12.D R201.1
NetR150_2: R150.2 R199.2 U32.A3(ILIM)
NetR193_2: R193.2 U23.5(SLV_ADDR)
NetR199_1: R199.1 R201.2

Not connected (* = marked no-connect by the designer): D16 4(CH3)* 5(CH4)* 6(NC)* 7(NC)*; J63 A2(TX1+)* A3(TX1-)* A8(SBU1)* A10(RX2-)* A11(RX2+)* B2(TX2+)* B3(TX2-)* B8(SBU2)* B10(RX1-)* B11(RX1+)*; U23 2(EN_SNK1)*

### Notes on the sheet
- USB_Type_C
- 52.3K default current limit = 1.1A
- 52.3K//23.1K = 16K, current limit 3A
- ILIM_5V_VBUS selects current limit of VBUS

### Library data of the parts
C147 C197 C199 = 1001168: as C111 on sheet 12 - MIPI to HDMI bridge
C187 C188 C198 C200 C201 = 1000006: as C112 on sheet 12 - MIPI to HDMI bridge
C195 C196 = 1000970: CAP CER 2.2UF 6.3V 20% X5R 0402; Part_Type: Capacitor; Manufacturer: TDK Corporation; Manufacturer_Part_Number: C1005X5R0J225M050BC; Manufacturer_Alt_1: Taiyo Yuden; Manufacturer_Alt_1_Part_Number: JMK105BJ225MV-F; Note: 14050756 = Digi No. for GE WDNU; Digi_PN: 14050493; Component_Life_Cycle_State: Reviewed; Area: 0.5; Project: ConnectCore i.MX6 module; Tolerance: 20
D16 = 1002593: TVS DIODE 5.5V 4V 10DFN; Part_Type: Circuit Protection; Manufacturer: Phillips NXP; Digi_PN: 17000143; Component_Life_Cycle_State: Created; Area: 7,24; Project: DIGI CC8X SOM
D21 = 1000231: DIODE SCHOTTKY 40V 1A SOD123; Part_Type: Diodes; Manufacturer: Diodes, Inc.; Digi_PN: 17000146; Component_Life_Cycle_State: Proven; Area: 8.28; Project: Adjustable Foundation
J63 = 1002675: USB 3.1 SHIELDED I/O RECP TYPE C GEN2; Part_Type: Connector; Manufacturer: Molex; Manufacturer_Part_Number: 201267-0005; Digi_PN: 18000775; Component_Life_Cycle_State: Created; Area: 86.57; Project: DIGI CC8X SOM
Q12 = 1000715: MOSFET N-CH 60V 115MA SOT-523F; Part_Type: Transistor; Manufacturer: Fairchild Semiconductor; Digi_PN: 17050797; Component_Life_Cycle_State: CAD Reviewed; Area: 3.06; Project: SmartMeter2; Note: 17050841 = Digi No. for GE WDNU
R51 R192 = 1000537: as R122 on sheet 12 - MIPI to HDMI bridge
R149 = 1001155: RES 47.0K OHM 1/16W 1% 0402 SMD; Part_Type: Resistor; Manufacturer: Vishay Dale; Manufacturer_Part_Number: CRCW040247K0FKED; Digi_PN: 13050646; Component_Life_Cycle_State: Reviewed; Area: 0,95; Project: CCWMX6_SBC board
R150 = 1000170: RES 52.3K OHM 1/10W 1% 0402 SMD; Part_Type: Resistor; Manufacturer: Panasonic - ECG; Manufacturer_Part_Number: ERJ-2RKF5232X; Digi_PN: 13000085; Component_Life_Cycle_State: Reviewed; Area: 0.95; Project: USB UART to USB Transceiver; Power_WV_SRF: 10
R193 = 1000480: RES 100K OHM 1/10W 1% 0402 SMD; Part_Type: Resistor; Manufacturer: Panasonic - ECG; Manufacturer_Part_Number: ERJ-2RKF1003X; Digi_PN: 13051063; Component_Life_Cycle_State: CAD Reviewed; Area: 0,95; Power_WV_SRF: 100
R199 = 1000079: as R130 on sheet 12 - MIPI to HDMI bridge
R201 = 1001149: RES 22.1K OHM 1/16W 1% 0402 SMD; Part_Type: Resistor; Manufacturer: Vishay Dale; Manufacturer_Part_Number: CRCW040222K1FKED; Digi_PN: 13050450; Component_Life_Cycle_State: Reviewed; Area: 0,95; Project: CCWMX6_SBC board; Power_WV_SRF: 0,063; Tolerance: ±100ppm/°C
R202 = 1000480: RES 100K OHM 1/10W 1% 0402 SMD; Part_Type: Resistor; Manufacturer: Panasonic - ECG; Manufacturer_Part_Number: ERJ-2RKF1003X; Digi_PN: 13051063; Component_Life_Cycle_State: CAD Reviewed; Area: 0.95; Project: KITT; Power_WV_SRF: 100
U23 = 1002585: IC USB PD TCPC PHY HX2QFN16; Manufacturer: NXP Semiconductors; Digi_PN: 16000125; Component_Life_Cycle_State: Reviewed; Area: 14.75; Project: DIGI CC8X SOM
U32 = 1002586: IC USB POWER SWITCH 16WLCSP; Manufacturer: NXP Semiconductors; Digi_PN: 16000126; Component_Life_Cycle_State: Reviewed; Area: 6.76; Project: DIGI CC8X SOM

## Sheet 15 - Bootstrap.SchDoc: Bootstrap
size A3; PageSetup: Record=PageOptions¦CenterHorizontal=True¦CenterVertical=True¦PrintScale=0.70¦XCorrection=1.00¦YCorrection=1.00¦PrintKind=0¦BorderSize=5000000¦LeftOffset=0¦BottomOffset=0¦Orientation=2¦PaperLength=4200¦PaperWidth=2970¦Scale=100¦PaperSource=7¦PrintQuality=600¦MediaType=1¦DitherType=10¦PaperKind=A4¦PrintScaleMode=1; Author: Juan Anzola; SheetNumber: 15; SheetTotal: 20

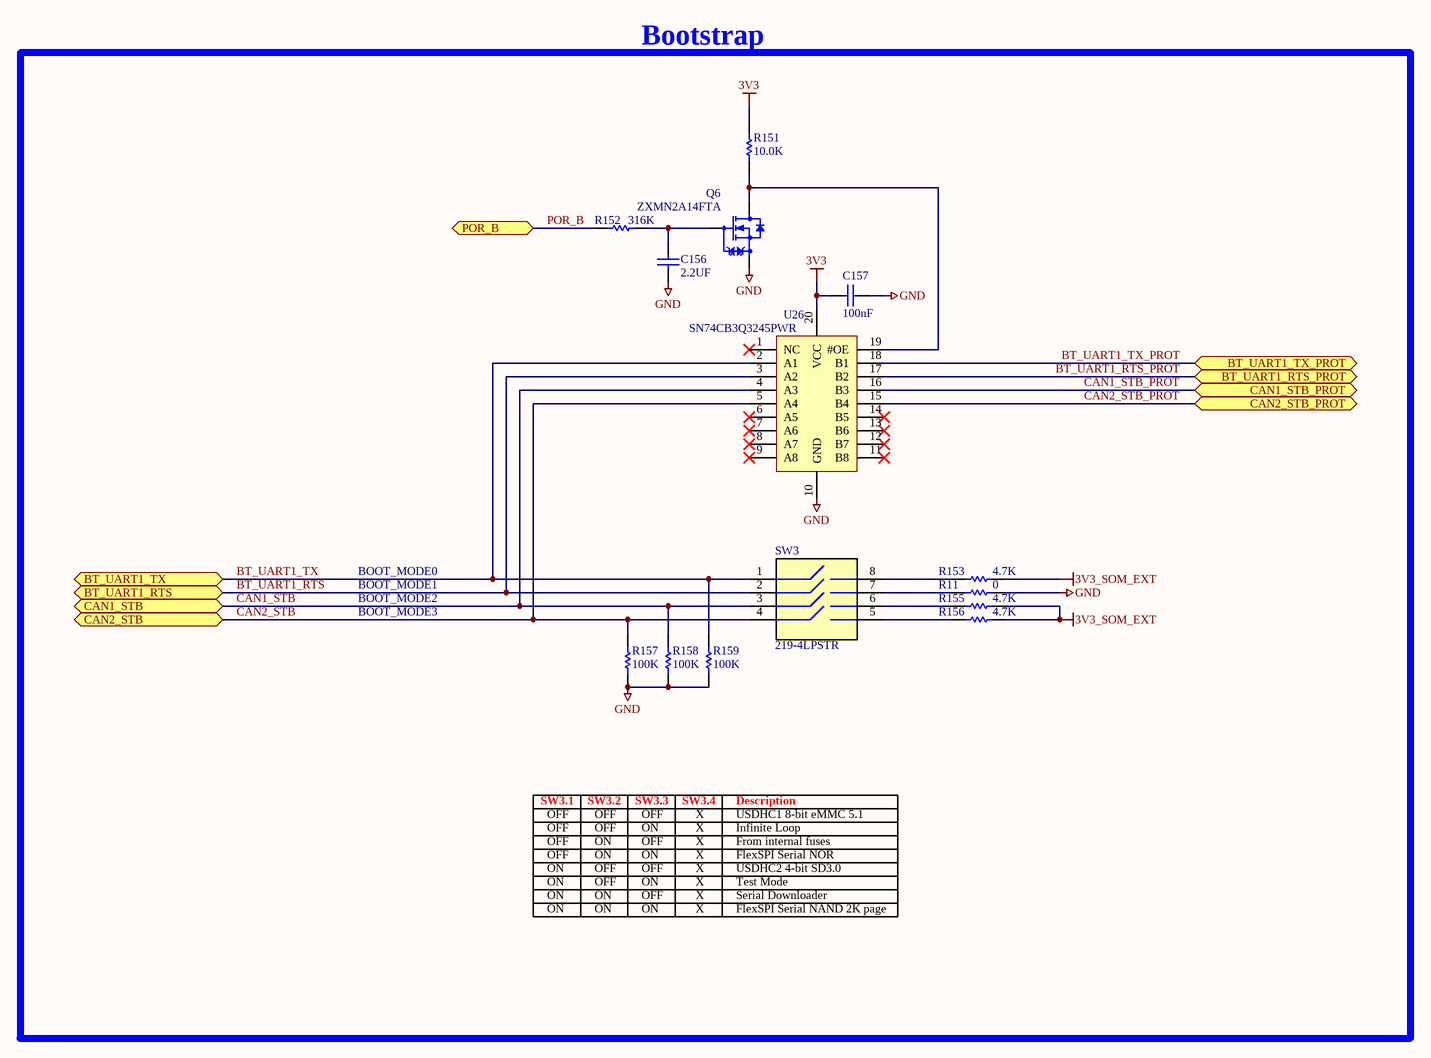
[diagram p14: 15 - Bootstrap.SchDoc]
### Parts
C156  2.2UF  [CAPC1608X90N]
C157  100nF  [CAPC1005X55N]
Q6  ZXMN2A14FTA  [SOT95P240X110_GSD-3N]
R11  0  [RESC1005X40N]
R151  10.0K  [RESC1005X40N]
R152  316K  [RESC1609X55N]
R153  4.7K  [RESC1005X40N]
R155  4.7K  [RESC1005X40N]
R156  4.7K  [RESC1005X40N]
R157  100K  [RESC1005X40N]
R158  100K  [RESC1005X40N]
R159  100K  [RESC1005X40N]
SW3  219-4LPSTR  [SOIC254P991X420-8N]
U26  SN74CB3Q3245PWR  [SOP65P640X120-20N]

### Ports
BT_UART1_RTS (bidir), BT_UART1_RTS_PROT (bidir), BT_UART1_TX (bidir), BT_UART1_TX_PROT (bidir), CAN1_STB (bidir), CAN1_STB_PROT (bidir), CAN2_STB (bidir), CAN2_STB_PROT (bidir), POR_B (bidir)

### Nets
3V3: C157.2 R151.2 U26.20(VCC)
3V3_SOM_EXT: R153.2 R155.2 R156.2
GND: C156.1 C157.1 Q6.S R11.2 R157.1 R158.1 R159.1 U26.10(GND)
BT_UART1_RTS: SW3.2 U26.3(A2) ; port BT_UART1_RTS
BT_UART1_RTS_PROT: U26.17(B2) ; port BT_UART1_RTS_PROT
BT_UART1_TX: R159.2 SW3.1 U26.2(A1) ; port BT_UART1_TX
BT_UART1_TX_PROT: U26.18(B1) ; port BT_UART1_TX_PROT
CAN1_STB: R158.2 SW3.3 U26.4(A3) ; port CAN1_STB
CAN1_STB_PROT: U26.16(B3) ; port CAN1_STB_PROT
CAN2_STB: R157.2 SW3.4 U26.5(A4) ; port CAN2_STB
CAN2_STB_PROT: U26.15(B4) ; port CAN2_STB_PROT
POR_B: R152.1 ; port POR_B
NetC156_2: C156.2 Q6.G R152.2
NetQ6_D: Q6.D R151.1 U26.19(#OE)
NetR11_1: R11.1 SW3.7
NetR153_1: R153.1 SW3.8
NetR155_1: R155.1 SW3.6
NetR156_1: R156.1 SW3.5

Not connected (* = marked no-connect by the designer): U26 1(NC)* 6(A5)* 7(A6)* 8(A7)* 9(A8)* 11(B8)* 12(B7)* 13(B6)* 14(B5)*

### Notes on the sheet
- Bootstrap
- BOOT_MODE0
- BOOT_MODE3
- BOOT_MODE2
- BOOT_MODE1
- SW3.1
- OFF
- SW3.2
- ON
- SW3.3
- SW3.4
- X
- USDHC1 8-bit eMMC 5.1
- Infinite Loop
- From internal fuses
- Description
- FlexSPI Serial NOR
- Serial Downloader
- USDHC2 4-bit SD3.0
- FlexSPI Serial NAND 2K page
- Test Mode

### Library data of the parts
C156 = 1001303: CAP CER 2.2UF 16V 10% X5R 0603; Part_Type: Capacitor; Manufacturer: TDK Corporation; Manufacturer_Part_Number: C1608X5R1C225K080AB; Digi_PN: 14050730; Component_Life_Cycle_State: Reviewed; Area: 2,27
C157 = 1000006: as C112 on sheet 12 - MIPI to HDMI bridge
Q6 = 1002855: as Q3-Q5 on sheet 12 - MIPI to HDMI bridge
R11 = 1000076: as R132 on sheet 12 - MIPI to HDMI bridge
R151 = 1000537: as R122 on sheet 12 - MIPI to HDMI bridge
R152 = 1001150: RES 316K OHM 1/10W 1% 0603 SMD; Part_Type: Resistor; Manufacturer: Yageo; Manufacturer_Part_Number: RC0603FR-07316KL; Digi_PN: 13050512; Component_Life_Cycle_State: Reviewed; Area: 1.5; Project: CCWMX6_SBC board; Power_WV_SRF: 100
R153 R155 R156 = 1000038: RES 4.7K OHM 1/10W 5% 0402 SMD; Part_Type: Resistor; Manufacturer: Panasonic - ECG; Manufacturer_Part_Number: ERJ-2GEJ472X; Digi_PN: 13050549; Component_Life_Cycle_State: Proven; Area: 0,95; Power_WV_SRF: 100; Tolerance: 5
R157-R159 = 1000480: as R193 on sheet 14 - USB Type C
SW3 = 1002122: SWITCH SLIDE DIP SPST 100MA 20V; Manufacturer: CTS; Digi_PN: 22000318; Component_Life_Cycle_State: Created; Area: 155
U26 = 1001368: IC SWITCH BUS 8BIT FET 20-TSSOP; Manufacturer: Texas Instruments; Digi_PN: 16052042; Component_Life_Cycle_State: Reviewed; Area: 48,18; Project: ConnectCore i.MX6x SOM

## Sheet 16 - Audio.SchDoc: Audio
size A3; PageSetup: Record=PageOptions¦CenterHorizontal=True¦CenterVertical=True¦PrintScale=0.70¦XCorrection=1.00¦YCorrection=1.00¦PrintKind=0¦BorderSize=5000000¦LeftOffset=0¦BottomOffset=0¦Orientation=2¦PaperLength=4200¦PaperWidth=2970¦Scale=100¦PaperSource=7¦PrintQuality=600¦MediaType=1¦DitherType=10¦PaperKind=A4¦PrintScaleMode=1; Author: Juan Anzola; SheetNumber: 16; SheetTotal: 20

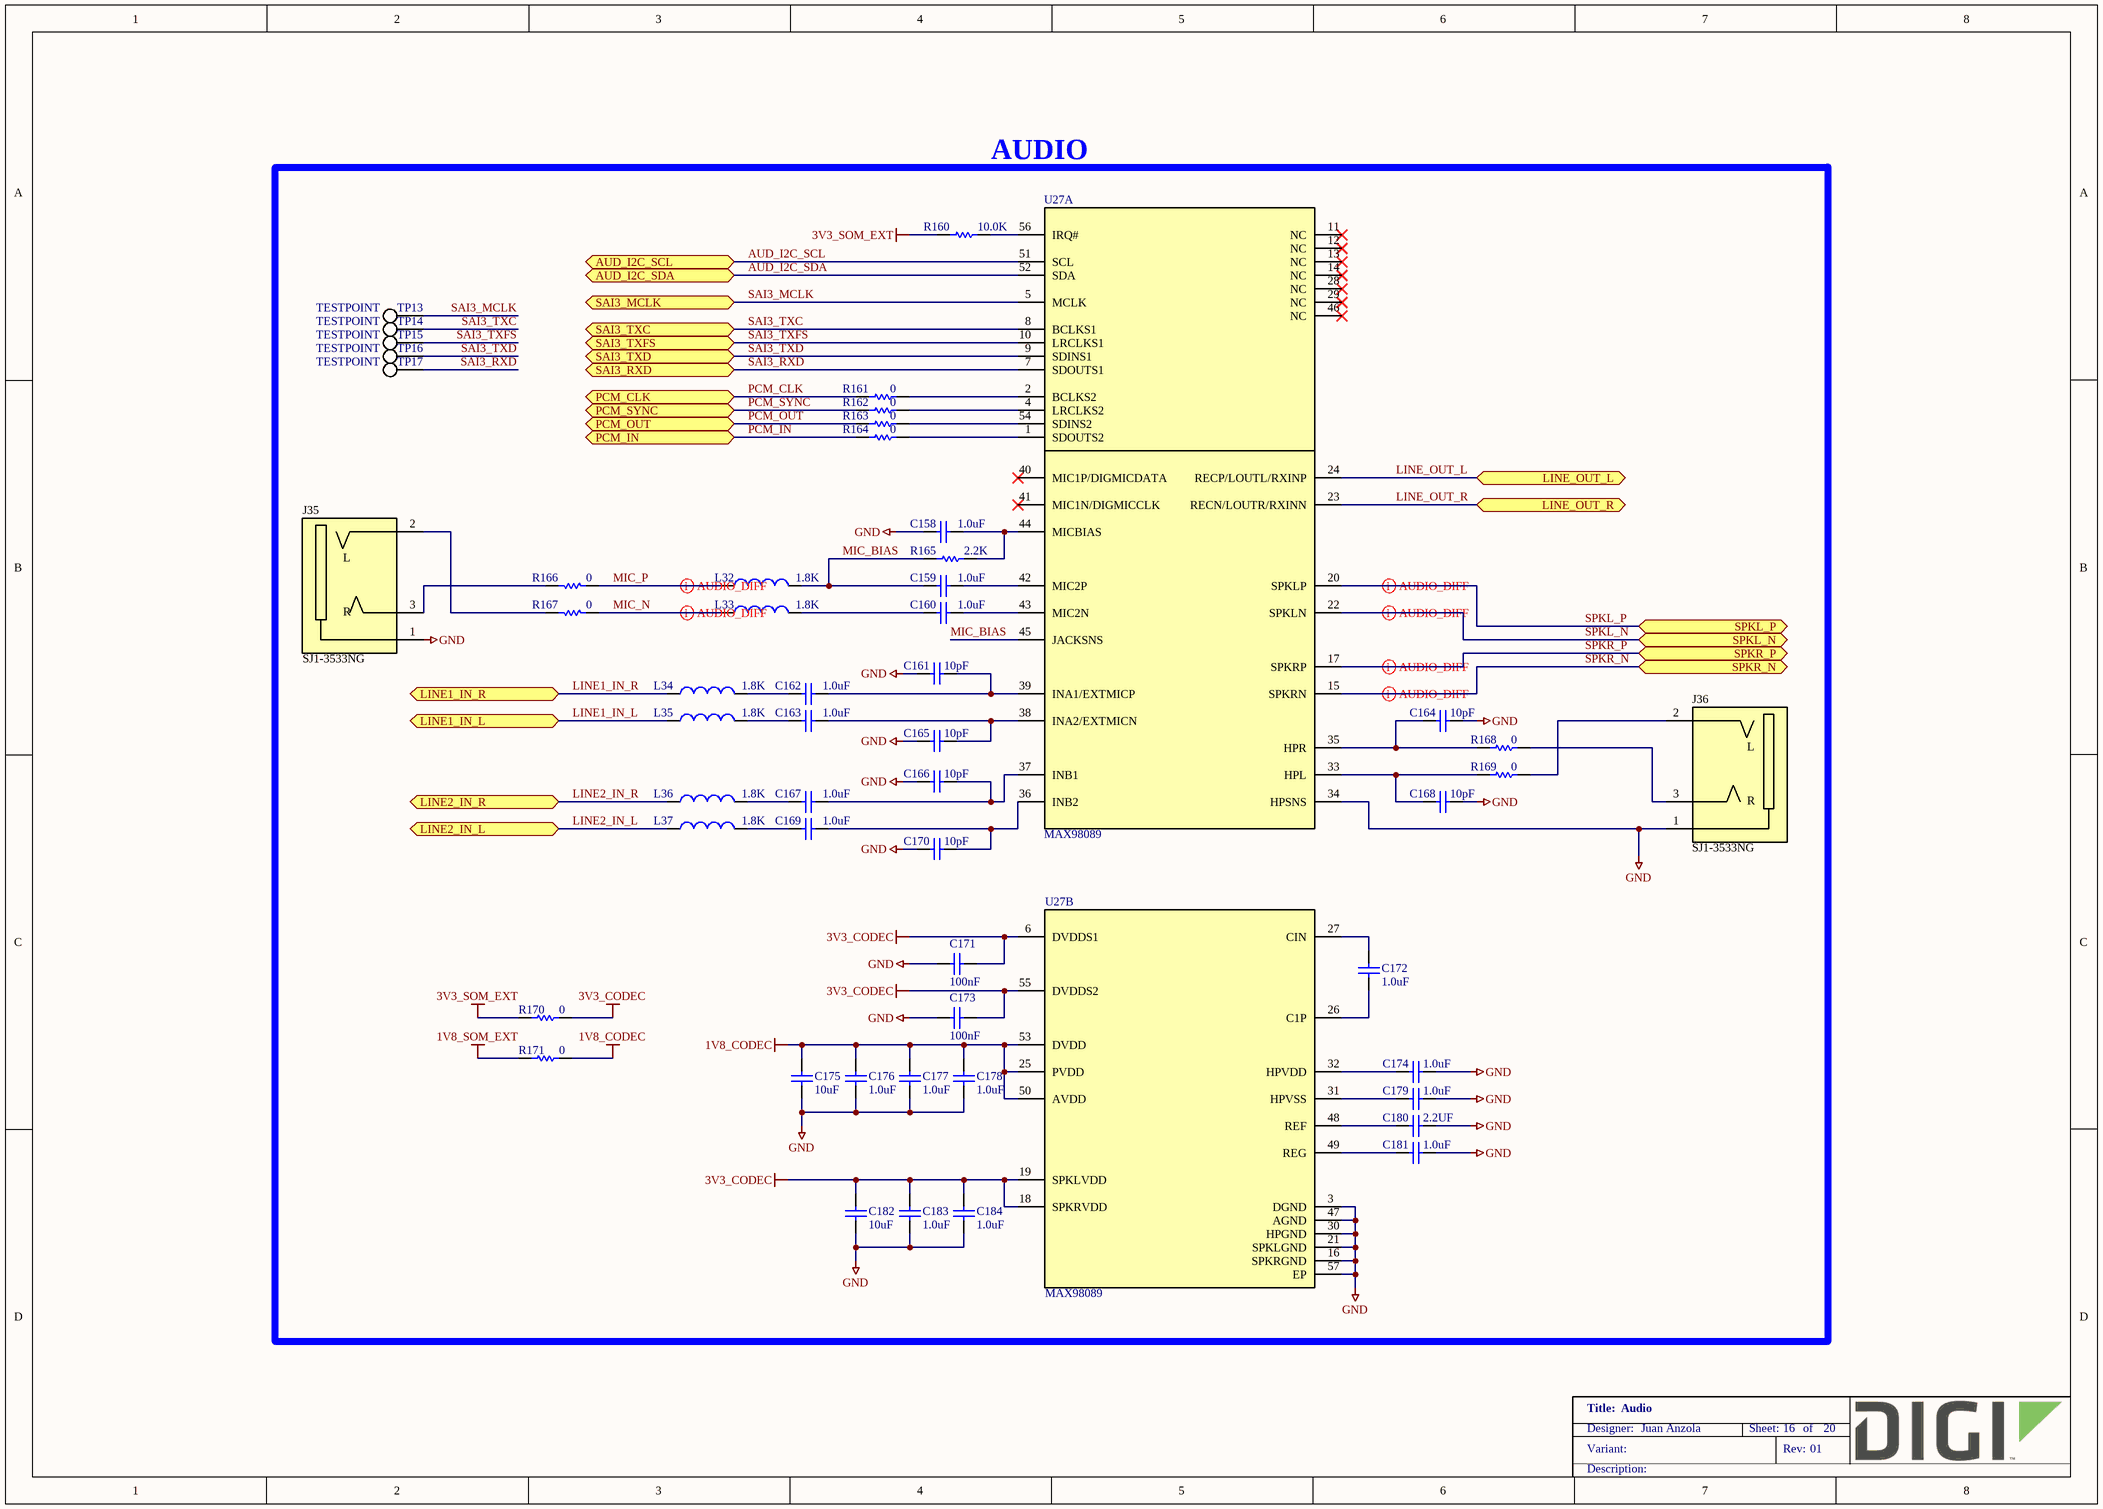
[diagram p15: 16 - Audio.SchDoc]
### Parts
C158  1.0uF  [CAPC1005X55N]
C159  1.0uF  [CAPC1005X55N]
C160  1.0uF  [CAPC1005X55N]
C161  10pF  [CAPC1005X55N]
C162  1.0uF  [CAPC1005X55N]
C163  1.0uF  [CAPC1005X55N]
C164  10pF  [CAPC1005X55N]
C165  10pF  [CAPC1005X55N]
C166  10pF  [CAPC1005X55N]
C167  1.0uF  [CAPC1005X55N]
C168  10pF  [CAPC1005X55N]
C169  1.0uF  [CAPC1005X55N]
C170  10pF  [CAPC1005X55N]
C171  100nF  [CAPC1005X55N]
C172  1.0uF  [CAPC1005X55N]
C173  100nF  [CAPC1005X55N]
C174  1.0uF  [CAPC1005X55N]
C175  10uF  [CAPC1005X55N]
C176  1.0uF  [CAPC1005X55N]
C177  1.0uF  [CAPC1005X55N]
C178  1.0uF  [CAPC1005X55N]
C179  1.0uF  [CAPC1005X55N]
C180  2.2UF  [CAPC1608X90N]
C181  1.0uF  [CAPC1005X55N]
C182  10uF  [CAPC1005X55N]
C183  1.0uF  [CAPC1005X55N]
C184  1.0uF  [CAPC1005X55N]
J35  SJ1-3533NG  [CUI_SJ1-3533N]
J36  SJ1-3533NG  [CUI_SJ1-3533N]
L32  1.8K  [INDC1005X60N]
L33  1.8K  [INDC1005X60N]
L34  1.8K  [INDC1005X60N]
L35  1.8K  [INDC1005X60N]
L36  1.8K  [INDC1005X60N]
L37  1.8K  [INDC1005X60N]
R160  10.0K  [RESC1005X40N]
R161  0  [RESC1005X40N]
R162  0  [RESC1005X40N]
R163  0  [RESC1005X40N]
R164  0  [RESC1005X40N]
R165  2.2K  [RESC1005X40N]
R166  0  [RESC1005X40N]
R167  0  [RESC1005X40N]
R168  0  [RESC1005X40N]
R169  0  [RESC1005X40N]
R170  0  [RESC1609X55N]
R171  0  [RESC1609X55N]
TP13  TESTPOINT  [TP0762]  (no BOM)
TP14  TESTPOINT  [TP0762]  (no BOM)
TP15  TESTPOINT  [TP0762]  (no BOM)
TP16  TESTPOINT  [TP0762]  (no BOM)
TP17  TESTPOINT  [TP0762]  (no BOM)
U27  MAX98089  [QFN40P700X700X80-57T560X560N]  (parts A,B of 2)

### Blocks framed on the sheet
AUDIO: C158-C184 J35 J36 L32-L37 R160-R171 TP13-TP17 U27

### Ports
AUD_I2C_SCL (bidir), AUD_I2C_SDA (bidir), LINE1_IN_L (bidir), LINE1_IN_R (bidir), LINE2_IN_L (bidir), LINE2_IN_R (bidir), LINE_OUT_L (bidir), LINE_OUT_R (bidir), PCM_CLK (bidir), PCM_IN (bidir), PCM_OUT (bidir), PCM_SYNC (bidir), SAI3_MCLK (bidir), SAI3_RXD (bidir), SAI3_TXC (bidir), SAI3_TXD (bidir), SAI3_TXFS (bidir), SPKL_N (bidir), SPKL_P (bidir), SPKR_N (bidir), SPKR_P (bidir)

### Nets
1V8_CODEC: C175.2 C176.1 C177.1 C178.1 R171.2 U27.25(PVDD) U27.50(AVDD) U27.53(DVDD)
1V8_SOM_EXT: R171.1
3V3_CODEC: C171.2 C173.2 C182.2 C183.1 C184.1 R170.2 U27.6(DVDDS1) U27.18(SPKRVDD) U27.19(SPKLVDD) U27.55(DVDDS2)
3V3_SOM_EXT: R160.1 R170.1
GND: C158.2 C161.2 C164.2 C165.2 C166.2 C168.2 C170.2 C171.1 C173.1 C174.1 C175.1 C176.2 C177.2 C178.2 C179.1 C180.1 C181.1 C182.1 C183.2 C184.2 J35.1 J36.1 U27.3(DGND) U27.16(SPKRGND) U27.21(SPKLGND) U27.30(HPGND) U27.34(HPSNS) U27.47(AGND) U27.57(EP)
AUD_I2C_SCL: U27.51(SCL) ; port AUD_I2C_SCL
AUD_I2C_SDA: U27.52(SDA) ; port AUD_I2C_SDA
LINE1_IN_L: L35.1 ; port LINE1_IN_L
LINE1_IN_R: L34.1 ; port LINE1_IN_R
LINE2_IN_L: L37.1 ; port LINE2_IN_L
LINE2_IN_R: L36.1 ; port LINE2_IN_R
LINE_OUT_L: U27.24(RECP/LOUTL/RXINP) ; port LINE_OUT_L
LINE_OUT_R: U27.23(RECN/LOUTR/RXINN) ; port LINE_OUT_R
MIC_BIAS: C159.2 L32.2 R165.1 U27.45(JACKSNS)
MIC_N: L33.1 R167.1
MIC_P: L32.1 R166.1
PCM_CLK: R161.1 ; port PCM_CLK
PCM_IN: R164.1 ; port PCM_IN
PCM_OUT: R163.1 ; port PCM_OUT
PCM_SYNC: R162.1 ; port PCM_SYNC
SAI3_MCLK: TP13.1 U27.5(MCLK) ; port SAI3_MCLK
SAI3_RXD: TP17.1 U27.7(SDOUTS1) ; port SAI3_RXD
SAI3_TXC: TP14.1 U27.8(BCLKS1) ; port SAI3_TXC
SAI3_TXD: TP16.1 U27.9(SDINS1) ; port SAI3_TXD
SAI3_TXFS: TP15.1 U27.10(LRCLKS1) ; port SAI3_TXFS
SPKL_N: U27.22(SPKLN) ; port SPKL_N
SPKL_P: U27.20(SPKLP) ; port SPKL_P
SPKR_N: U27.15(SPKRN) ; port SPKR_N
SPKR_P: U27.17(SPKRP) ; port SPKR_P
NetC158_1: C158.1 R165.2 U27.44(MICBIAS)
NetC159_1: C159.1 U27.42(MIC2P)
NetC160_1: C160.1 U27.43(MIC2N)
NetC160_2: C160.2 L33.2
NetC161_1: C161.1 C162.1 U27.39(INA1/EXTMICP)
NetC162_2: C162.2 L34.2
NetC163_1: C163.1 C165.1 U27.38(INA2/EXTMICN)
NetC163_2: C163.2 L35.2
NetC164_1: C164.1 R168.1 U27.35(HPR)
NetC166_1: C166.1 C167.1 U27.37(INB1)
NetC167_2: C167.2 L36.2
NetC168_1: C168.1 R169.1 U27.33(HPL)
NetC169_1: C169.1 C170.1 U27.36(INB2)
NetC169_2: C169.2 L37.2
NetC172_1: C172.1 U27.27(CIN)
NetC172_2: C172.2 U27.26(C1P)
NetC174_2: C174.2 U27.32(HPVDD)
NetC179_2: C179.2 U27.31(HPVSS)
NetC180_2: C180.2 U27.48(REF)
NetC181_2: C181.2 U27.49(REG)
NetJ35_2: J35.2 R167.2
NetJ35_3: J35.3 R166.2
NetJ36_2: J36.2 R169.2
NetJ36_3: J36.3 R168.2
NetR160_2: R160.2 U27.56(IRQ#)
NetR161_2: R161.2 U27.2(BCLKS2)
NetR162_2: R162.2 U27.4(LRCLKS2)
NetR163_2: R163.2 U27.54(SDINS2)
NetR164_2: R164.2 U27.1(SDOUTS2)

Not connected (* = marked no-connect by the designer): U27 11(NC)* 12(NC)* 13(NC)* 14(NC)* 28(NC)* 29(NC)* 40(MIC1P/DIGMICDATA)* 41(MIC1N/DIGMICCLK)* 46(NC)*

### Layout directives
differential pair: MIC_N, MIC_P, SPKL_N, SPKL_P, SPKR_N, SPKR_P

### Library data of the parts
C158-C160 C162 C163 C167 C169 = 1001167: CAP CER 1UF 10V 10% X5R 0402; Part_Type: Capacitor; Manufacturer: Murata; Manufacturer_Part_Number: GRM155R61A105KE15D; Digi_PN: 14050399; Component_Life_Cycle_State: Reviewed; Area: 0,95
C161 C164-C166 C168 C170 = 1001541: CAP CER 10PF 50V 5% NP0 0402; Part_Type: Capacitor; Manufacturer: Murata; Manufacturer_Part_Number: GRM1555C1H100JA01D; Note: 14050750 = Digi No. for GE WDNU; Digi_PN: 14050362; Component_Life_Cycle_State: Reviewed; Area: 0,95; Project: KITT v0.4; Tolerance: 5; Temp_Coef: C0G, NP0
C171 C173 = 1000006: CAP 100nF 16V 10% X7R 0402; Part_Type: Capacitor; Manufacturer: Murata; Manufacturer_Part_Number: GRM155R71C104KA88D; Digi_PN: 14050552; Component_Life_Cycle_State: CAD Reviewed; Area: 0.95; Project: KITT; Tolerance: 10
C172 C174 C176-C179 C181 C183 C184 = 1001167: as C139 on sheet 13 - USB HUB
C175 C182 = 1001168: as C111 on sheet 12 - MIPI to HDMI bridge
C180 = 1001303: CAP CER 2.2UF 16V 10% X5R 0603; Part_Type: Capacitor; Manufacturer: TDK Corporation; Manufacturer_Part_Number: C1608X5R1C225K080AB; Digi_PN: 14050730; Component_Life_Cycle_State: Reviewed; Area: 2,27; Project: Pinnacle
J35 J36 = 1002596: CONN JACK STEREO 3.5MM R/A; Part_Type: Connector; Manufacturer: CUI Inc.; Digi_PN: 18000594; Component_Life_Cycle_State: Reviewed; Area: 163.02; Project: CCWMX6_SBC board
L32-L37 = 1002041: FERRITE BEAD 1.8 KOHM 0402 1LN; Manufacturer: Murata; Manufacturer_Part_Number: BLM15HD182SN1D; Digi_PN: 21000461; Component_Life_Cycle_State: Reviewed; Area: 2.2; Project: iMX6UL+PMIC
R160 = 1000537: as R122 on sheet 12 - MIPI to HDMI bridge
R161-R164 R166-R169 = 1000076: RES 0.0 OHM 1/10W 0402 SMD; Part_Type: Resistor; Manufacturer: Panasonic - ECG; Manufacturer_Part_Number: ERJ-2GE0R00X; Component_Life_Cycle_State: Proven; Area: 0.95; Project: Adjustable Foundation; Power_WV_SRF: 10; Digi_PN: 13050387
R165 = 1001156: RES 2.20K OHM 1/16W 1% 0402 SMD; Part_Type: Resistor; Manufacturer: Yageo; Manufacturer_Part_Number: RC0402FR-072K2L; Note: 13051099 = Digi No. for GE WDNU; Digi_PN: 13050699; Component_Life_Cycle_State: Reviewed; Area: 0,95; Project: CCWMX6_SBC board
R170 R171 = 1000208: as R141 on sheet 13 - USB HUB
TP13-TP17 = CAD0011: TEST POINT 30MIL PAD SMT; Component_Life_Cycle_State: Reviewed; Area: 0,58; Project: CLC
U27 = 1002001: IC CODEC AUDIO FLEXSOUND 56TQFN; Manufacturer: Maxim; Manufacturer_Part_Number: MAX98089ETN+T; Component_Life_Cycle_State: Reviewed; Area: 49; Project: iMX6UL+PMIC; Digi_PN: 16052036

## Sheet 17 - I2C, XBee, MIKROBUS.SchDoc: I2C, XBee, MIKROBUS
size A3; PageSetup: Record=PageOptions¦CenterHorizontal=True¦CenterVertical=True¦PrintScale=0.70¦XCorrection=1.00¦YCorrection=1.00¦PrintKind=0¦BorderSize=5000000¦LeftOffset=0¦BottomOffset=0¦Orientation=2¦PaperLength=4200¦PaperWidth=2970¦Scale=100¦PaperSource=7¦PrintQuality=600¦MediaType=1¦DitherType=10¦PaperKind=A4¦PrintScaleMode=1; Author: Juan Anzola; SheetNumber: 17; SheetTotal: 20

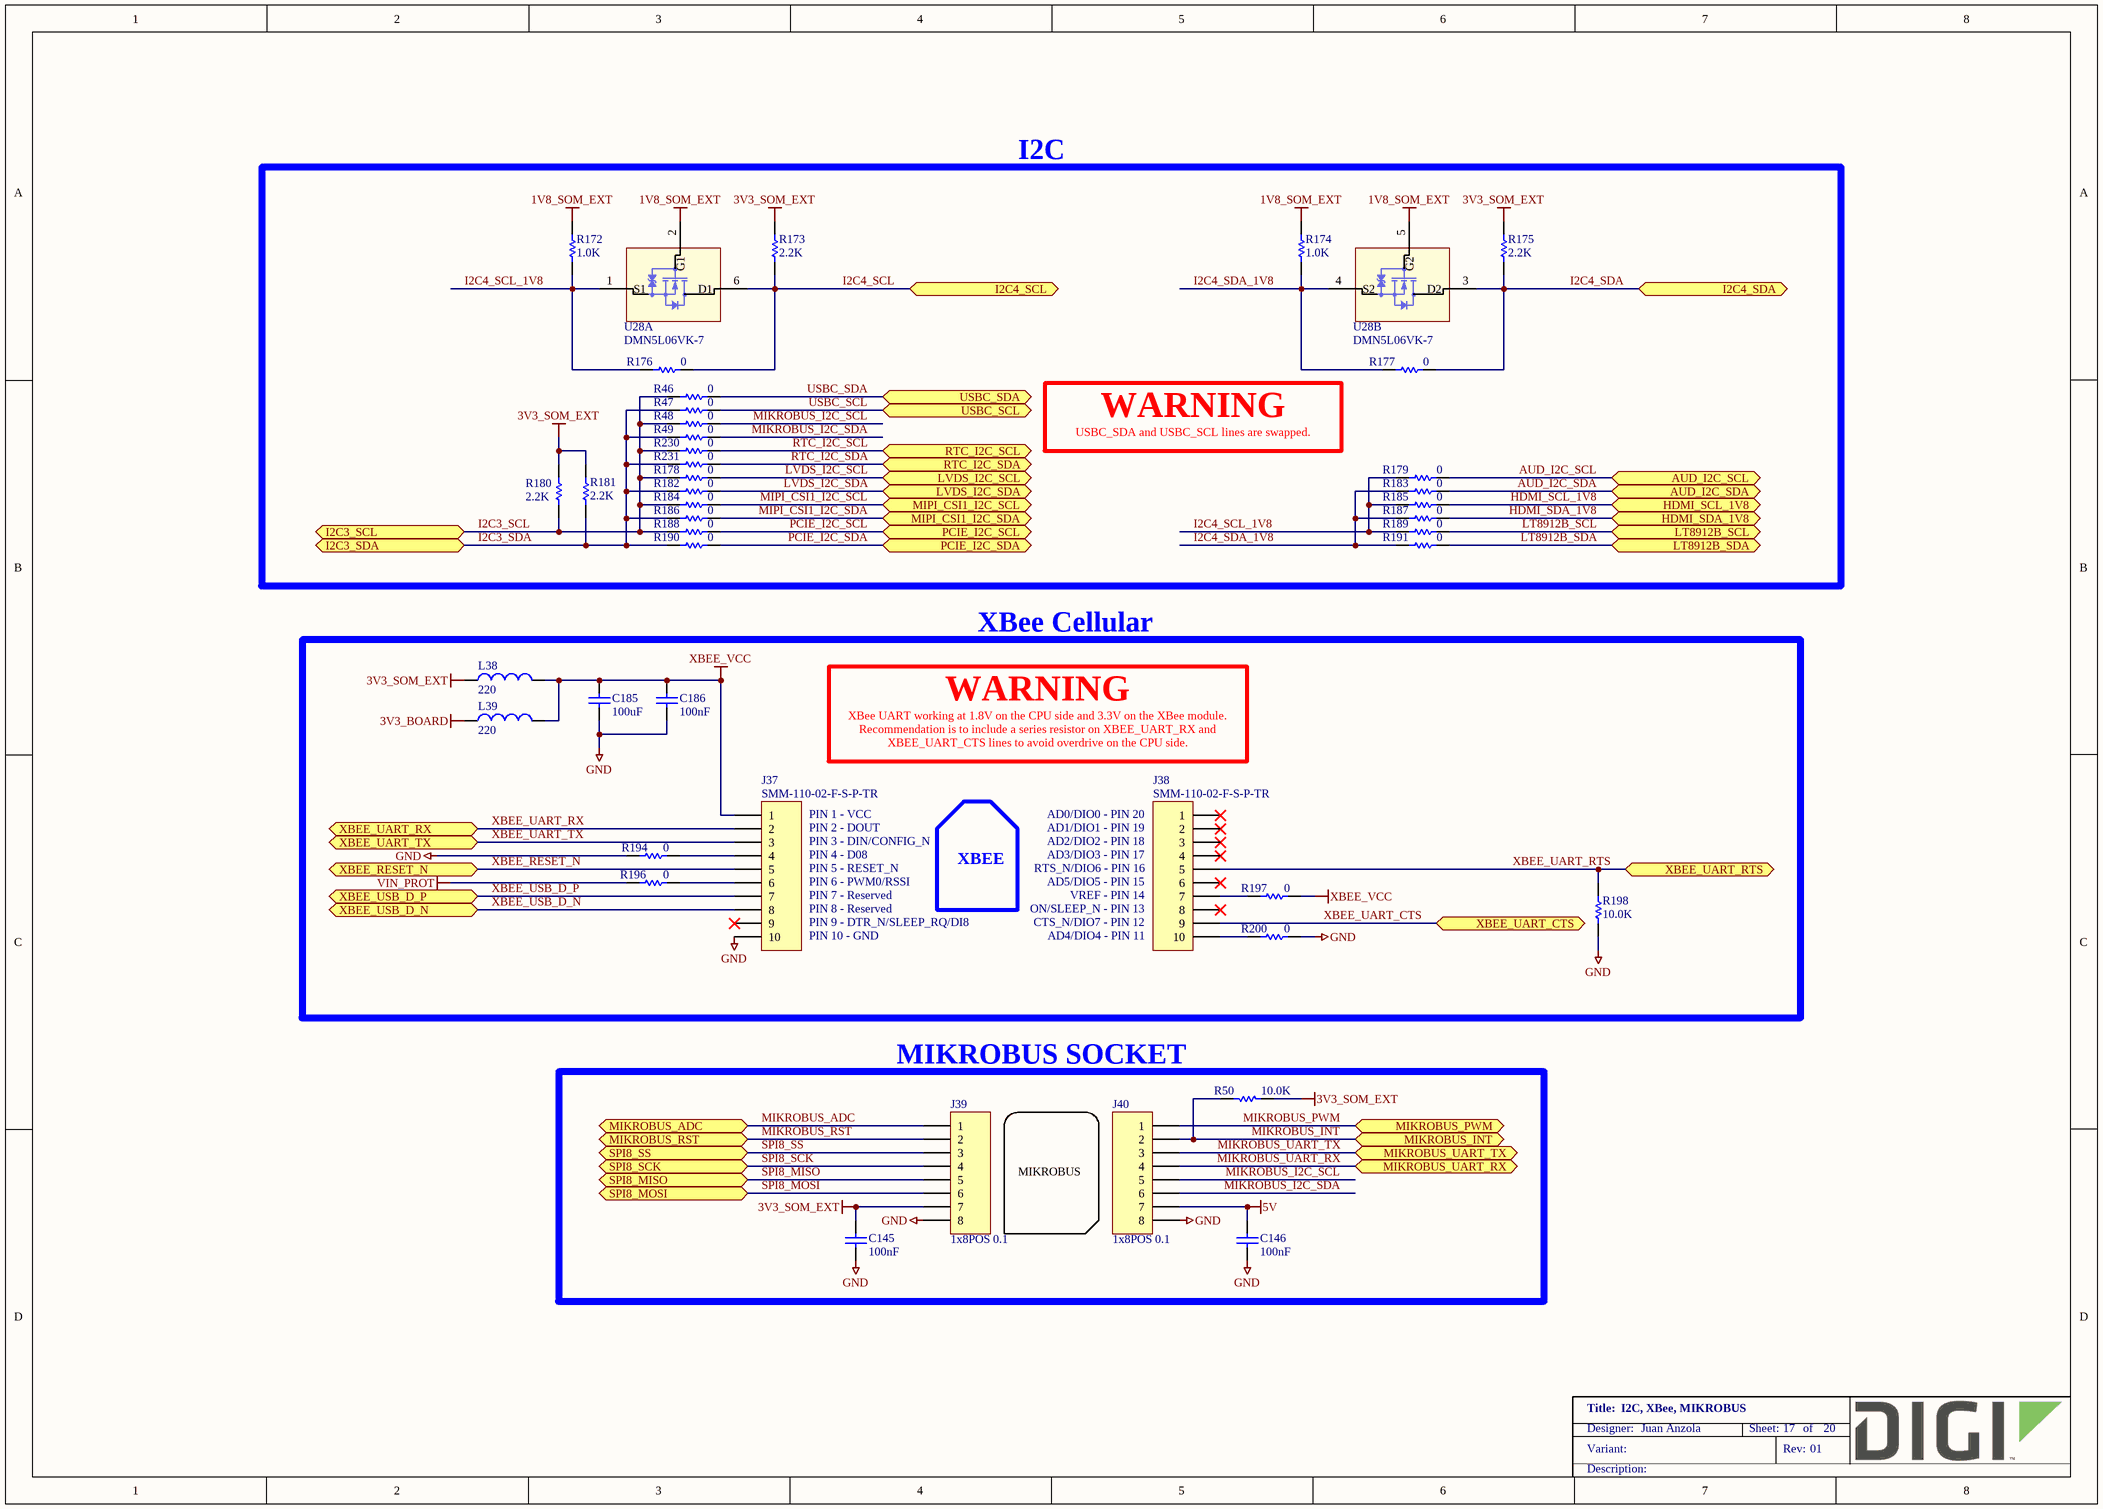
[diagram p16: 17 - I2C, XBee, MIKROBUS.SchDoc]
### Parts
C145  100nF  [CAPC1005X55N]
C146  100nF  [CAPC1005X55N]
C185  100uF  [CAPC3216X190N]
C186  100nF  [CAPC1005X55N]
J37  SMM-110-02-F-S-P-TR  [Samtec_SMM-110-02-F-S]
J38  SMM-110-02-F-S-P-TR  [Samtec_SMM-110-02-F-S]
J39  1x8POS 0.1  [J8_THT_0.1_FEMALE]
J40  1x8POS 0.1  [J8_THT_0.1_FEMALE]
L38  220  [INDC2013X110N]
L39  220  [INDC2013X110N]
R46  0  [RESC1005X40N]
R47  0  [RESC1005X40N]
R48  0  [RESC1005X40N]
R49  0  [RESC1005X40N]
R50  10.0K  [RESC1005X40N]
R172  1.0K  [RESC1005X40N]
R173  2.2K  [RESC1005X40N]
R174  1.0K  [RESC1005X40N]
R175  2.2K  [RESC1005X40N]
R176  0  [RESC1005X40N]
R177  0  [RESC1005X40N]
R178  0  [RESC1005X40N]
R179  0  [RESC1005X40N]
R180  2.2K  [RESC1005X40N]
R181  2.2K  [RESC1005X40N]
R182  0  [RESC1005X40N]
R183  0  [RESC1005X40N]
R184  0  [RESC1005X40N]
R185  0  [RESC1005X40N]
R186  0  [RESC1005X40N]
R187  0  [RESC1005X40N]
R188  0  [RESC1005X40N]
R189  0  [RESC1005X40N]
R190  0  [RESC1005X40N]
R191  0  [RESC1005X40N]
R194  0  [RESC1005X40N]
R196  0  [RESC1005X40N]
R197  0  [RESC1005X40N]
R198  10.0K  [RESC1005X40N]
R200  0  [RESC1005X40N]
R230  0  [RESC1005X40N]
R231  0  [RESC1005X40N]
U28  DMN5L06VK-7  [SOTFL50P160X60-6N]  (parts A,B of 2)

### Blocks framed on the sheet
I2C: R46-R49 R172-R191 R230 R231 U28
XBee Cellular: C185 C186 J37 J38 L38 L39 R194 R196-R198 R200
MIKROBUS SOCKET: C145 C146 J39 J40 R50

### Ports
AUD_I2C_SCL (bidir), AUD_I2C_SDA (bidir), HDMI_SCL_1V8 (bidir), HDMI_SDA_1V8 (bidir), I2C3_SCL (bidir), I2C3_SDA (bidir), I2C4_SCL (bidir), I2C4_SDA (bidir), LT8912B_SCL (bidir), LT8912B_SDA (bidir), LVDS_I2C_SCL (bidir), LVDS_I2C_SDA (bidir), MIKROBUS_ADC (bidir), MIKROBUS_INT (bidir), MIKROBUS_PWM (bidir), MIKROBUS_RST (bidir), MIKROBUS_UART_RX (bidir), MIKROBUS_UART_TX (bidir), MIPI_CSI1_I2C_SCL (bidir), MIPI_CSI1_I2C_SDA (bidir), PCIE_I2C_SCL (bidir), PCIE_I2C_SDA (bidir), RTC_I2C_SCL (bidir), RTC_I2C_SDA (bidir), SPI8_MISO (bidir), SPI8_MOSI (bidir), SPI8_SCK (bidir), SPI8_SS (bidir), USBC_SCL (bidir), USBC_SDA (bidir), XBEE_RESET_N (bidir), XBEE_UART_CTS (bidir), XBEE_UART_RTS (bidir), XBEE_UART_RX (bidir), XBEE_UART_TX (bidir), XBEE_USB_D_N (bidir), XBEE_USB_D_P (bidir)

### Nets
1V8_SOM_EXT: R172.2 R174.2 U28.2(G1) U28.5(G2)
3V3_BOARD: L39.1
3V3_SOM_EXT: C145.2 J39.7 L38.1 R50.2 R173.2 R175.2 R180.2 R181.2
5V: C146.1 J40.7
GND: C145.1 C146.2 C185.1 C186.1 J37.10 J39.8 J40.8 R194.1 R198.1 R200.2
VIN_PROT: R196.1
XBEE_VCC: C185.2 C186.2 J37.1 L38.2 L39.2 R197.2
AUD_I2C_SCL: R179.2 ; port AUD_I2C_SCL
AUD_I2C_SDA: R183.2 ; port AUD_I2C_SDA
HDMI_SCL_1V8: R185.2 ; port HDMI_SCL_1V8
HDMI_SDA_1V8: R187.2 ; port HDMI_SDA_1V8
I2C3_SCL: R46.1 R48.1 R178.1 R180.1 R184.1 R188.1 R230.1 ; port I2C3_SCL
I2C3_SDA: R47.1 R49.1 R181.1 R182.1 R186.1 R190.1 R231.1 ; port I2C3_SDA
I2C4_SCL: R173.1 R176.2 U28.6(D1) ; port I2C4_SCL
I2C4_SCL_1V8: R172.1 R176.1 R179.1 R185.1 R189.1 U28.1(S1)
I2C4_SDA: R175.1 R177.2 U28.3(D2) ; port I2C4_SDA
I2C4_SDA_1V8: R174.1 R177.1 R183.1 R187.1 R191.1 U28.4(S2)
LT8912B_SCL: R189.2 ; port LT8912B_SCL
LT8912B_SDA: R191.2 ; port LT8912B_SDA
LVDS_I2C_SCL: R178.2 ; port LVDS_I2C_SCL
LVDS_I2C_SDA: R182.2 ; port LVDS_I2C_SDA
MIKROBUS_ADC: J39.1 ; port MIKROBUS_ADC
MIKROBUS_I2C_SCL: J40.5 R48.2
MIKROBUS_I2C_SDA: J40.6 R49.2
MIKROBUS_INT: J40.2 R50.1 ; port MIKROBUS_INT
MIKROBUS_PWM: J40.1 ; port MIKROBUS_PWM
MIKROBUS_RST: J39.2 ; port MIKROBUS_RST
MIKROBUS_UART_RX: J40.4 ; port MIKROBUS_UART_RX
MIKROBUS_UART_TX: J40.3 ; port MIKROBUS_UART_TX
MIPI_CSI1_I2C_SCL: R184.2 ; port MIPI_CSI1_I2C_SCL
MIPI_CSI1_I2C_SDA: R186.2 ; port MIPI_CSI1_I2C_SDA
PCIE_I2C_SCL: R188.2 ; port PCIE_I2C_SCL
PCIE_I2C_SDA: R190.2 ; port PCIE_I2C_SDA
RTC_I2C_SCL: R230.2 ; port RTC_I2C_SCL
RTC_I2C_SDA: R231.2 ; port RTC_I2C_SDA
SPI8_MISO: J39.5 ; port SPI8_MISO
SPI8_MOSI: J39.6 ; port SPI8_MOSI
SPI8_SCK: J39.4 ; port SPI8_SCK
SPI8_SS: J39.3 ; port SPI8_SS
USBC_SCL: R47.2 ; port USBC_SCL
USBC_SDA: R46.2 ; port USBC_SDA
XBEE_RESET_N: J37.5 ; port XBEE_RESET_N
XBEE_UART_CTS: J38.9 ; port XBEE_UART_CTS
XBEE_UART_RTS: J38.5 R198.2 ; port XBEE_UART_RTS
XBEE_UART_RX: J37.2 ; port XBEE_UART_RX
XBEE_UART_TX: J37.3 ; port XBEE_UART_TX
XBEE_USB_D_N: J37.8 ; port XBEE_USB_D_N
XBEE_USB_D_P: J37.7 ; port XBEE_USB_D_P
NetJ37_4: J37.4 R194.2
NetJ37_6: J37.6 R196.2
NetJ38_7: J38.7 R197.1
NetJ38_10: J38.10 R200.1

Not connected (* = marked no-connect by the designer): J37 9*; J38 1* 2* 3* 4* 6* 8*

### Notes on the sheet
- WARNING
- USBC_SDA and USBC_SCL lines are swapped.
- XBee UART working at 1.8V on the CPU side and 3.3V on the XBee module. Recommendation is to include a series resistor on XBEE_UART_RX and XBEE_UART_CTS lines to avoid overdrive on the CPU side.
- (near J37) PIN 1 - VCC
- (near J37) PIN 2 - DOUT
- (near J37) PIN 3 - DIN/CONFIG_N
- (near J37) PIN 4 - D08
- (near J38) AD0/DIO0 - PIN 20
- (near J38) AD1/DIO1 - PIN 19
- (near J38) AD2/DIO2 - PIN 18
- (near J38) AD3/DIO3 - PIN 17
- (near J37) PIN 5 - RESET_N
- (near J37) PIN 6 - PWM0/RSSI
- (near J37) PIN 7 - Reserved
- (near J37) PIN 8 - Reserved
- XBEE
- (near J38) RTS_N/DIO6 - PIN 16
- (near J38) AD5/DIO5 - PIN 15
- (near J38) VREF - PIN 14
- (near J38) ON/SLEEP_N - PIN 13
- (near J37) PIN 9 - DTR_N/SLEEP_RQ/DI8
- (near J37) PIN 10 - GND
- (near J38) CTS_N/DIO7 - PIN 12
- (near J38) AD4/DIO4 - PIN 11
- MIKROBUS

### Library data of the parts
C145 = 1000006: CAP 100nF 16V 10% X7R 0402; Part_Type: Capacitor; Manufacturer: Murata; Manufacturer_Part_Number: GRM155R71C104KA88D; Digi_PN: 14050552; Component_Life_Cycle_State: CAD Reviewed; Area: 0,95; Tolerance: 10
C146 C186 = 1000006: as C112 on sheet 12 - MIPI to HDMI bridge
C185 = 1000566: CAP CER 100UF 10V 20% X5R 1206; Part_Type: Capacitor; Manufacturer: TDK Corporation; Manufacturer_Part_Number: C3216X5R1A107M; Digi_PN: 14050666; Component_Life_Cycle_State: Reviewed; Area: 7.47; Project: GSM Cell PCB
J37 J38 = 1001495: CONN RCPT 2MM 10POS SMD; Part_Type: Connector; Manufacturer: Samtec; Digi_PN: 19050036; Component_Life_Cycle_State: Reviewed; Area: 105; Project: CCWMX6_SBC board
J39 J40 = 1002848: CONN HDR 8POS 0.1 GOLD PCB; Part_Type: Connector; Manufacturer: Sullins; Manufacturer_Part_Number: PPPC081LFBN-RC; Digi_PN: 18000876; Component_Life_Cycle_State: Pending
L38 L39 = 1001174: as L22-L25 on sheet 13 - USB HUB
R46-R49 R176 R177 R230 R231 = 1000076: as R132 on sheet 12 - MIPI to HDMI bridge
R50 R198 = 1000537: as R122 on sheet 12 - MIPI to HDMI bridge
R172 R174 = 1000079: as R130 on sheet 12 - MIPI to HDMI bridge
R173 R175 = 1001156: as R131 on sheet 12 - MIPI to HDMI bridge
R178 R179 R182-R191 R194 R196 R197 R200 = 1000076: as R161-R164 on sheet 16 - Audio
R180 R181 = 1001156: RES 2.20K OHM 1/16W 1% 0402 SMD; Part_Type: Resistor; Manufacturer: Yageo; Manufacturer_Part_Number: RC0402FR-072K2L; Digi_PN: 13050699; Component_Life_Cycle_State: Reviewed; Area: 0.95; Project: CCWMX6_SBC board; Note: 13051099 = Digi No. for GE WDNU
U28 = 1002493: MOSFET 2N-CH 30V 0.1A ES6; Part_Type: Transistor; Manufacturer: Diodes, Inc.; Digi_PN: 17000134; Component_Life_Cycle_State: Reviewed; Area: 4,88

## Sheet 18 - Expansion connectors, LEDs and buttons.SchDoc: Expansion connectors, LEDs and buttons
size A3; PageSetup: Record=PageOptions¦CenterHorizontal=True¦CenterVertical=True¦PrintScale=0.70¦XCorrection=1.00¦YCorrection=1.00¦PrintKind=0¦BorderSize=5000000¦LeftOffset=0¦BottomOffset=0¦Orientation=2¦PaperLength=4200¦PaperWidth=2970¦Scale=100¦PaperSource=7¦PrintQuality=600¦MediaType=1¦DitherType=10¦PaperKind=A4¦PrintScaleMode=1; Author: Juan Anzola; SheetNumber: 18; SheetTotal: 20

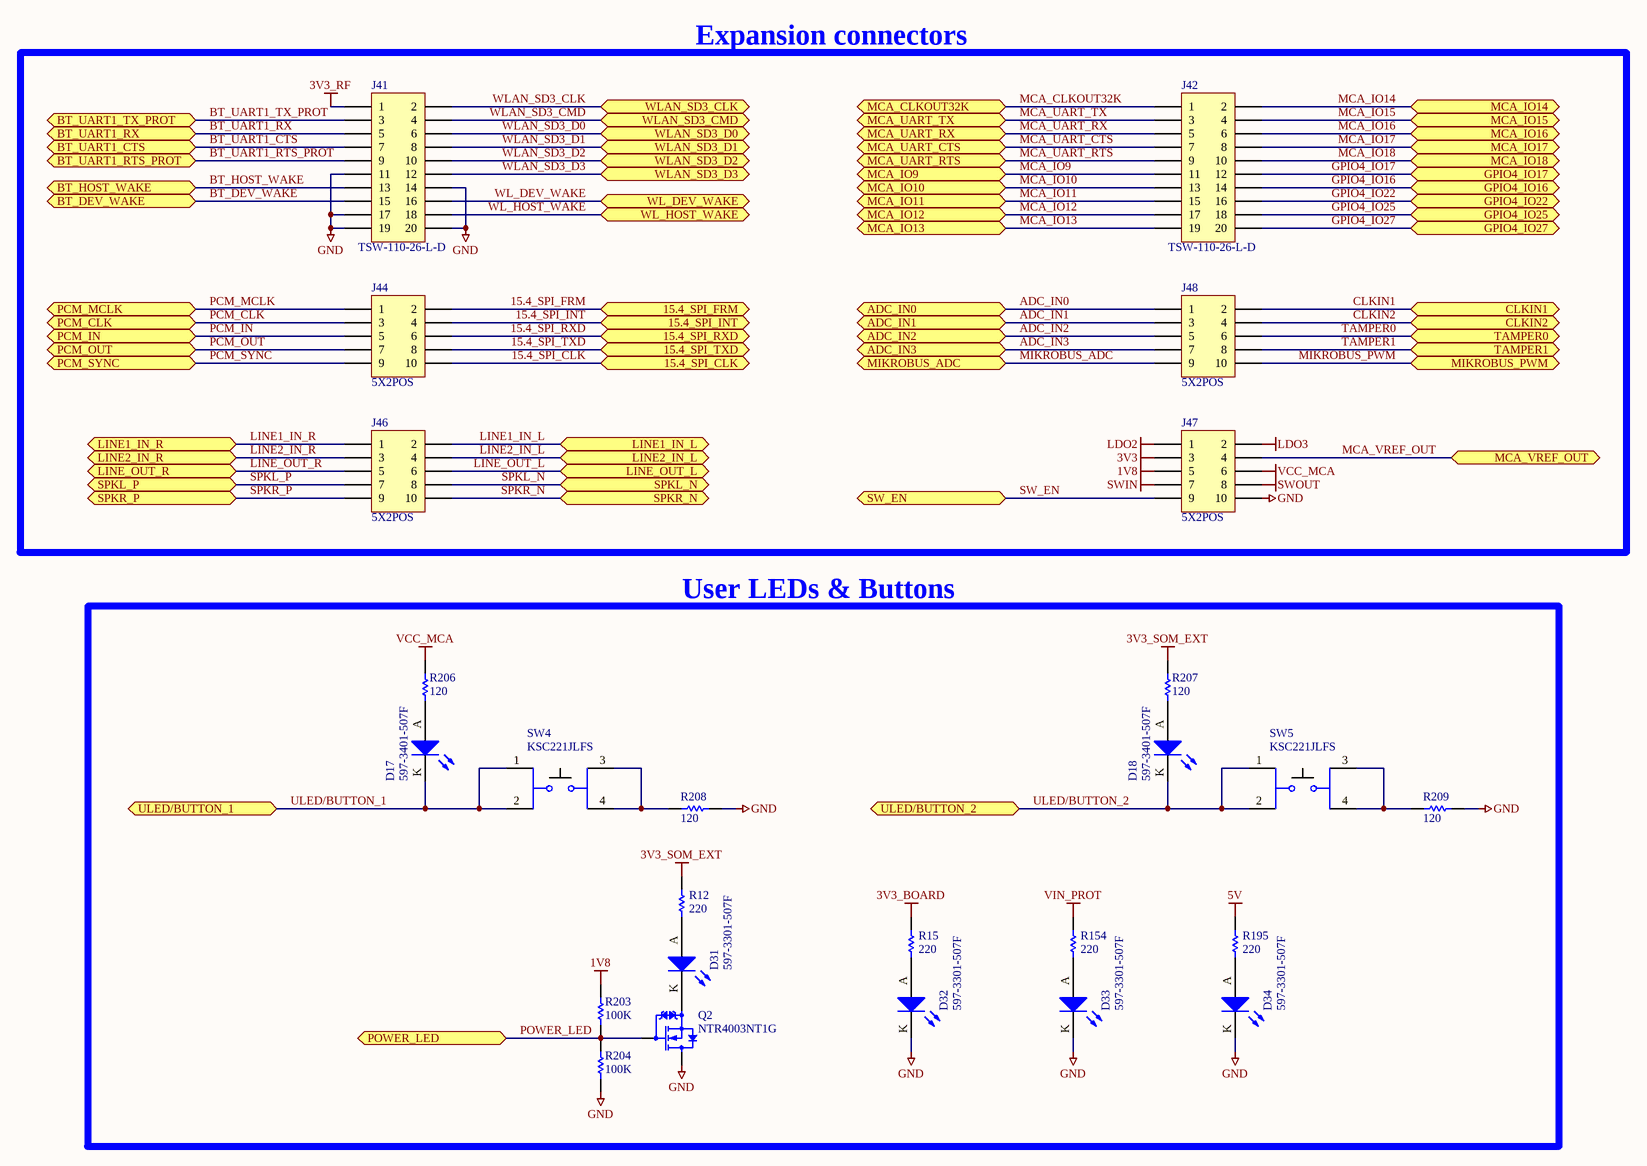
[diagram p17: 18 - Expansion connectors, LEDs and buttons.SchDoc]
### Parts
D17  597-3401-507F  [LEDM3020X130N_YELLOW]
D18  597-3401-507F  [LEDM3020X130N_YELLOW]
D31  597-3301-507F  [LEDM3020X130N]
D32  597-3301-507F  [LEDM3020X130N]
D33  597-3301-507F  [LEDM3020X130N]
D34  597-3301-507F  [LEDM3020X130N]
J41  TSW-110-26-L-D  [SAMTEC_TSW-110-26-L-D]
J42  TSW-110-26-L-D  [SAMTEC_TSW-110-26-L-D]
J44  5X2POS  [MOLEX_87914-1016]
J46  5X2POS  [MOLEX_87914-1016]
J47  5X2POS  [MOLEX_87914-1016]
J48  5X2POS  [MOLEX_87914-1016]
Q2  NTR4003NT1G  [SOT95P240X110_GSD-3N]
R12  220  [RESC1005X40N]
R15  220  [RESC1005X40N]
R154  220  [RESC1005X40N]
R195  220  [RESC1005X40N]
R203  100K  [RESC1005X40N]
R204  100K  [RESC1005X40N]
R206  120  [RESC1005X40N]
R207  120  [RESC1005X40N]
R208  120  [RESC1005X40N]
R209  120  [RESC1005X40N]
SW4  KSC221JLFS  [SW_KSC221J]
SW5  KSC221JLFS  [SW_KSC221J]

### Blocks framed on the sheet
Expansion connectors: J41 J42 J44 J46-J48
User LEDs & Buttons: D17 D18 D31-D34 Q2 R12 R15 R154 R195 R203 R204 R206-R209 SW4 SW5

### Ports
15.4_SPI_CLK (bidir), 15.4_SPI_FRM (bidir), 15.4_SPI_INT (bidir), 15.4_SPI_RXD (bidir), 15.4_SPI_TXD (bidir), ADC_IN0 (bidir), ADC_IN1 (bidir), ADC_IN2 (bidir), ADC_IN3 (bidir), BT_DEV_WAKE (bidir), BT_HOST_WAKE (bidir), BT_UART1_CTS (bidir), BT_UART1_RTS_PROT (bidir), BT_UART1_RX (bidir), BT_UART1_TX_PROT (bidir), CLKIN1 (bidir), CLKIN2 (bidir), GPIO4_IO16 (bidir), GPIO4_IO17 (bidir), GPIO4_IO22 (bidir), GPIO4_IO25 (bidir), GPIO4_IO27 (bidir), LINE1_IN_L (bidir), LINE1_IN_R (bidir), LINE2_IN_L (bidir), LINE2_IN_R (bidir), LINE_OUT_L (bidir), LINE_OUT_R (bidir), MCA_CLKOUT32K (bidir), MCA_IO9 (bidir), MCA_IO10 (bidir), MCA_IO11 (bidir), MCA_IO12 (bidir), MCA_IO13 (bidir), MCA_IO14 (bidir), MCA_IO15 (bidir), MCA_IO16 (bidir), MCA_IO17 (bidir), MCA_IO18 (bidir), MCA_UART_CTS (bidir), MCA_UART_RTS (bidir), MCA_UART_RX (bidir), MCA_UART_TX (bidir), MCA_VREF_OUT (bidir), MIKROBUS_ADC (bidir), MIKROBUS_PWM (bidir), PCM_CLK (bidir), PCM_IN (bidir), PCM_MCLK (bidir), PCM_OUT (bidir), PCM_SYNC (bidir), POWER_LED (bidir), SPKL_N (bidir), SPKL_P (bidir), SPKR_N (bidir), SPKR_P (bidir), SW_EN (bidir), TAMPER0 (bidir), TAMPER1 (bidir), ULED/BUTTON_1 (bidir), ULED/BUTTON_2 (bidir), WL_DEV_WAKE (bidir), WL_HOST_WAKE (bidir), WLAN_SD3_CLK (bidir), WLAN_SD3_CMD (bidir), WLAN_SD3_D0 (bidir), WLAN_SD3_D1 (bidir), WLAN_SD3_D2 (bidir), WLAN_SD3_D3 (bidir)

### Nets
1V8: J47.5 R203.1
3V3: J47.3
3V3_BOARD: R15.2
3V3_RF: J41.1
3V3_SOM_EXT: R12.2 R207.2
5V: R195.2
GND: D32.K D33.K D34.K J41.11 J41.14 J41.17 J41.19 J41.20 J47.10 Q2.D R204.2 R208.1 R209.1
LDO2: J47.1
LDO3: J47.2
SWIN: J47.7
SWOUT: J47.8
VCC_MCA: J47.6 R206.2
VIN_PROT: R154.2
15.4_SPI_CLK: J44.10 ; port 15.4_SPI_CLK
15.4_SPI_FRM: J44.2 ; port 15.4_SPI_FRM
15.4_SPI_INT: J44.4 ; port 15.4_SPI_INT
15.4_SPI_RXD: J44.6 ; port 15.4_SPI_RXD
15.4_SPI_TXD: J44.8 ; port 15.4_SPI_TXD
ADC_IN0: J48.1 ; port ADC_IN0
ADC_IN1: J48.3 ; port ADC_IN1
ADC_IN2: J48.5 ; port ADC_IN2
ADC_IN3: J48.7 ; port ADC_IN3
BT_DEV_WAKE: J41.15 ; port BT_DEV_WAKE
BT_HOST_WAKE: J41.13 ; port BT_HOST_WAKE
BT_UART1_CTS: J41.7 ; port BT_UART1_CTS
BT_UART1_RTS_PROT: J41.9 ; port BT_UART1_RTS_PROT
BT_UART1_RX: J41.5 ; port BT_UART1_RX
BT_UART1_TX_PROT: J41.3 ; port BT_UART1_TX_PROT
CLKIN1: J48.2 ; port CLKIN1
CLKIN2: J48.4 ; port CLKIN2
GPIO4_IO16: J42.14 ; port GPIO4_IO16
GPIO4_IO17: J42.12 ; port GPIO4_IO17
GPIO4_IO22: J42.16 ; port GPIO4_IO22
GPIO4_IO25: J42.18 ; port GPIO4_IO25
GPIO4_IO27: J42.20 ; port GPIO4_IO27
LINE1_IN_L: J46.2 ; port LINE1_IN_L
LINE1_IN_R: J46.1 ; port LINE1_IN_R
LINE2_IN_L: J46.4 ; port LINE2_IN_L
LINE2_IN_R: J46.3 ; port LINE2_IN_R
LINE_OUT_L: J46.6 ; port LINE_OUT_L
LINE_OUT_R: J46.5 ; port LINE_OUT_R
MCA_CLKOUT32K: J42.1 ; port MCA_CLKOUT32K
MCA_IO9: J42.11 ; port MCA_IO9
MCA_IO10: J42.13 ; port MCA_IO10
MCA_IO11: J42.15 ; port MCA_IO11
MCA_IO12: J42.17 ; port MCA_IO12
MCA_IO13: J42.19 ; port MCA_IO13
MCA_IO14: J42.2 ; port MCA_IO14
MCA_IO15: J42.4 ; port MCA_IO15
MCA_IO16: J42.6 ; port MCA_IO16
MCA_IO17: J42.8 ; port MCA_IO17
MCA_IO18: J42.10 ; port MCA_IO18
MCA_UART_CTS: J42.7 ; port MCA_UART_CTS
MCA_UART_RTS: J42.9 ; port MCA_UART_RTS
MCA_UART_RX: J42.5 ; port MCA_UART_RX
MCA_UART_TX: J42.3 ; port MCA_UART_TX
MCA_VREF_OUT: J47.4 ; port MCA_VREF_OUT
MIKROBUS_ADC: J48.9 ; port MIKROBUS_ADC
MIKROBUS_PWM: J48.10 ; port MIKROBUS_PWM
PCM_CLK: J44.3 ; port PCM_CLK
PCM_IN: J44.5 ; port PCM_IN
PCM_MCLK: J44.1 ; port PCM_MCLK
PCM_OUT: J44.7 ; port PCM_OUT
PCM_SYNC: J44.9 ; port PCM_SYNC
POWER_LED: Q2.G R203.2 R204.1 ; port POWER_LED
SPKL_N: J46.8 ; port SPKL_N
SPKL_P: J46.7 ; port SPKL_P
SPKR_N: J46.10 ; port SPKR_N
SPKR_P: J46.9 ; port SPKR_P
SW_EN: J47.9 ; port SW_EN
TAMPER0: J48.6 ; port TAMPER0
TAMPER1: J48.8 ; port TAMPER1
ULED/BUTTON_1: D17.K SW4.1 SW4.2 ; port ULED/BUTTON_1
ULED/BUTTON_2: D18.K SW5.1 SW5.2 ; port ULED/BUTTON_2
WL_DEV_WAKE: J41.16 ; port WL_DEV_WAKE
WL_HOST_WAKE: J41.18 ; port WL_HOST_WAKE
WLAN_SD3_CLK: J41.2 ; port WLAN_SD3_CLK
WLAN_SD3_CMD: J41.4 ; port WLAN_SD3_CMD
WLAN_SD3_D0: J41.6 ; port WLAN_SD3_D0
WLAN_SD3_D1: J41.8 ; port WLAN_SD3_D1
WLAN_SD3_D2: J41.10 ; port WLAN_SD3_D2
WLAN_SD3_D3: J41.12 ; port WLAN_SD3_D3
NetD17_A: D17.A R206.1
NetD18_A: D18.A R207.1
NetD31_A: D31.A R12.1
NetD31_K: D31.K Q2.S
NetD32_A: D32.A R15.1
NetD33_A: D33.A R154.1
NetD34_A: D34.A R195.1
NetR208_2: R208.2 SW4.3 SW4.4
NetR209_2: R209.2 SW5.3 SW5.4

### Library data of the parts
D17 D18 = 1001188: LED YELLOW 588NM 1208 SMD; Manufacturer: Dialight; Note: 17050842 = Digi No. for GE WDNU; Digi_PN: 17050387; Component_Life_Cycle_State: Reviewed; Area: 6
D31-D34 = 1001189: LED GREEN 573NM 1208 SMD; Manufacturer: Dialight; Digi_PN: 17050183; Component_Life_Cycle_State: Reviewed; Area: 6; Project: CCWMX6_SBC board; Note: 17050846 = Digi PN for GE WDNU II
J41 J42 = 1002751: CONN HEADER VERT 20POS 2.54MM; Part_Type: Connector; Manufacturer: Samtec; Digi_PN: 01730020; Component_Life_Cycle_State: Created; Area: 150,08
J44 J46-J48 = 1001335: CONN HEADER 10POS DL VERT T/H; Part_Type: Connector; Manufacturer: Molex; Manufacturer_Part_Number: 87914-1016; Note: Check symbol pin-out upon reactivation; Digi_PN: 18000793; Component_Life_Cycle_State: Abandoned; Area: 63,5
Q2 = 1000306: MOSFET N-CH 30V 500MA SOT-23; Part_Type: Transistor; Manufacturer: On Semiconductor; Digi_PN: 17050809; Component_Life_Cycle_State: Proven; Area: 10,92
R12 R15 R154 R195 = 1001154: RES 220 OHM 1/16W 1% 0402 SMD; Part_Type: Resistor; Manufacturer: Yageo; Manufacturer_Part_Number: RC0402FR-07220RL; Digi_PN: 13050623; Component_Life_Cycle_State: Reviewed; Area: 0.95; Project: CCWMX6_SBC board
R203 R204 = 1000480: as R202 on sheet 14 - USB Type C
R206-R209 = 1001158: RES 120 OHM 1/16W 1% 0402 SMD; Part_Type: Resistor; Manufacturer: Yageo; Manufacturer_Part_Number: RC0402FR-07120RL; Note: 13051102 = Digi No. for GE WDNU; Digi_PN: 13050832; Component_Life_Cycle_State: Reviewed; Area: 0,95; Project: CCWMX6_SBC board
SW4 SW5 = 1001124: SWITCH TACTILE SPST-NO 0.05A 32V; Manufacturer: ITT; Digi_PN: 22000059; Component_Life_Cycle_State: Reviewed; Area: 37; Project: CCWMX6_SBC board; Note: 22000295 = Digi No. for GE WDNU

## Sheet 19 - System power rails, GPIO table.SchDoc: System power rails, GPIO table
size A3; PageSetup: Record=PageOptions¦CenterHorizontal=True¦CenterVertical=True¦PrintScale=1.01¦XCorrection=1.00¦YCorrection=1.00¦PrintKind=0¦BorderSize=5000000¦LeftOffset=0¦BottomOffset=0¦Orientation=2¦PaperLength=4200¦PaperWidth=2970¦Scale=100¦PaperSource=15¦PrintQuality=600¦MediaType=1¦DitherType=10¦PrintScaleMode=1¦PaperKind=A3¦PaperIndex=8; Author: Juan Anzola; SheetNumber: 19; SheetTotal: 20

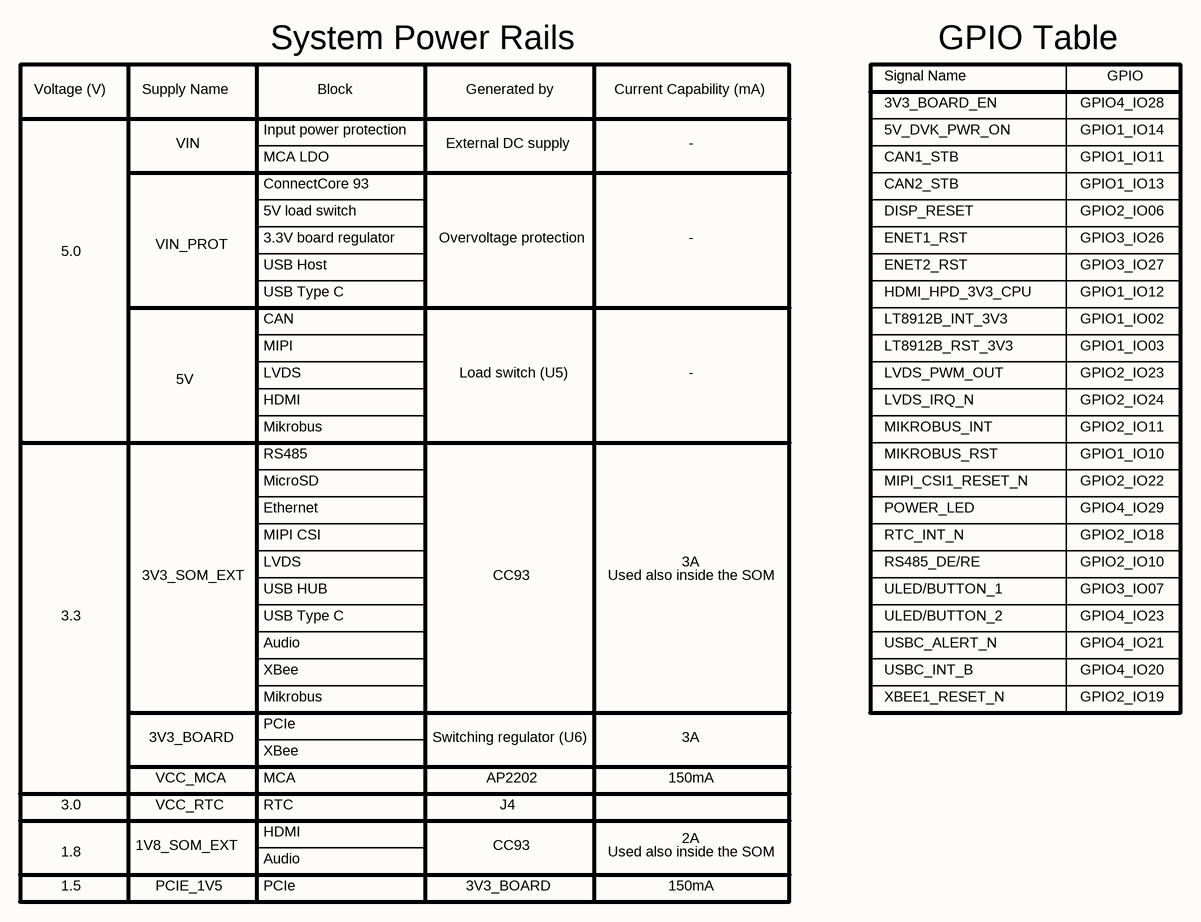
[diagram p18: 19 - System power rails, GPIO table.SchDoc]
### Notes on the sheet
- Voltage (V)
- Supply Name
- System Power Rails
- Block
- Generated by
- Current Capability (mA)
- Signal Name
- GPIO Table
- GPIO
- VIN
- Input power protection
- External DC supply
- -
- 3V3_BOARD_EN
- 5V_DVK_PWR_ON
- GPIO1_IO14
- GPIO4_IO28
- MCA LDO
- ConnectCore 93
- 5V load switch
- CAN1_STB
- CAN2_STB
- DISP_RESET
- GPIO1_IO13
- GPIO1_IO11
- GPIO2_IO06
- 5.0
- VIN_PROT
- USB Host
- 3.3V board regulator
- Overvoltage protection
- ENET1_RST
- ENET2_RST
- GPIO3_IO26
- GPIO3_IO27
- USB Type C
- CAN
- MIPI
- LT8912B_INT_3V3
- HDMI_HPD_3V3_CPU
- LT8912B_RST_3V3
- GPIO1_IO02
- GPIO1_IO03
- GPIO1_IO12
- 5V
- HDMI
- LVDS
- Load switch (U5)
- LVDS_PWM_OUT
- LVDS_IRQ_N
- GPIO2_IO24
- GPIO2_IO23
- MicroSD
- Mikrobus
- RS485
- MIPI_CSI1_RESET_N
- MIKROBUS_INT
- MIKROBUS_RST
- GPIO2_IO22
- GPIO2_IO11
- GPIO1_IO10
- Ethernet
- MIPI CSI
- POWER_LED
- RTC_INT_N
- GPIO4_IO29
- GPIO2_IO18
- 3.3
- 3V3_SOM_EXT
- USB HUB
- CC93
- Used also inside the SOM
- 3A
- ULED/BUTTON_1
- RS485_DE/RE
- ULED/BUTTON_2
- GPIO2_IO10
- GPIO3_IO07
- GPIO4_IO23
- Audio
- XBee
- USBC_ALERT_N
- USBC_INT_B
- GPIO4_IO21
- GPIO4_IO20
- 3V3_BOARD
- PCIe
- Switching regulator (U6)
- XBEE1_RESET_N
- GPIO2_IO19
- 3.0
- VCC_MCA
- VCC_RTC
- MCA
- RTC
- AP2202
- J4
- 150mA
- 1.8
- 1.5
- 1V8_SOM_EXT
- PCIE_1V5
- 2A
